# LEF file generated by Abstract Generator version 6.1.5
#
# Contains LEF for all bins.
# Options:   [ ] Antenna
#            [ ] Geometry
#            [x] Technology
# Design rule Document No.TD-LO40-DR-2001  Rev: 3R
# Antenna rule Document No.TD-LO40-DR-2004 Rev: 0T


VERSION 5.7 ;
NAMESCASESENSITIVE ON ;
BUSBITCHARS "[]" ;
DIVIDERCHAR "/" ;
UNITS
  DATABASE MICRONS 1000 ;
END UNITS

MANUFACTURINGGRID 0.001 ;
USEMINSPACING OBS OFF ;

PROPERTYDEFINITIONS
  LAYER LEF58_ENCLOSURE STRING ;
  LAYER LEF58_ENCLOSUREEDGE STRING ;
  LAYER LEF57_ANTENNAGATEPLUSDIFF STRING ;
  LAYER LEF58_ARRAYSPACING STRING ;
  LAYER LEF58_SPACING STRING ;
END PROPERTYDEFINITIONS

LAYER GT
  TYPE	MASTERSLICE ;
END GT

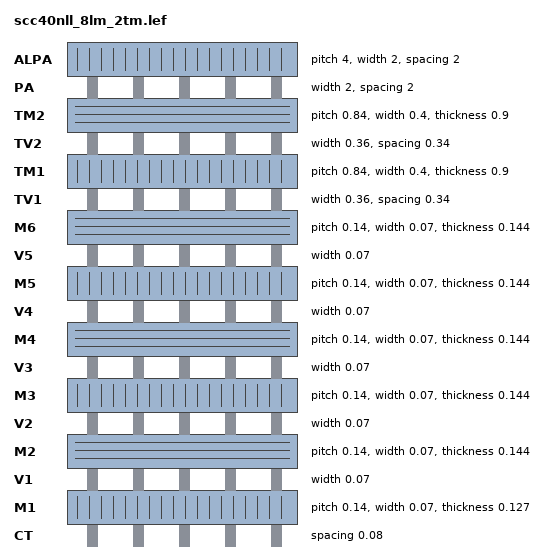
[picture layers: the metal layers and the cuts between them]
LAYER CT
  TYPE CUT ;
  SPACING 0.08 ;
  PROPERTY LEF58_ENCLOSUREEDGE "ENCLOSUREEDGE ABOVE 0.015 WIDTH 0.11 PARALLEL 0.265 WITHIN 0.085 ;"  ;
END CT

LAYER M1
  TYPE		ROUTING ;
  DIRECTION	VERTICAL ;
  PITCH		0.14 ;
  OFFSET	0.07 ;
  WIDTH		0.07 ;
  MINWIDTH 0.07 ;
  MAXWIDTH 4.5 ;
  MINSTEP 0.07 MAXEDGES 1 ;
  SPACINGTABLE TWOWIDTHS
    WIDTH     0.00                   0.070   0.080   0.120   0.30 
    WIDTH     0.215    PRL 0.2950    0.080   0.080   0.140   0.30 
    WIDTH     0.695    PRL 0.5950    0.120   0.140   0.120   0.30
    WIDTH     1.495    PRL 1.4950    0.300   0.300   0.300   0.30 ;
  MINIMUMCUT 2 WIDTH 0.24 WITHIN 0.16 FROMABOVE ;
  MINIMUMCUT 2 WIDTH 0.24 WITHIN 0.16 FROMABOVE LENGTH 0.24 WITHIN 1.105 ;
  MINIMUMCUT 2 WIDTH 0.26 FROMABOVE ;
  MINIMUMCUT 3 WIDTH 0.52 FROMABOVE ;
  MINIMUMCUT 4 WIDTH 0.645 FROMABOVE ;
  PROPERTY LEF58_SPACING "SPACING 0.08 ENDOFLINE 0.09 WITHIN 0.02 MINLENGTH 0.07 TWOSIDES
  PARALLELEDGE 0.08 WITHIN 0.065 ;" ;
  RESISTANCE	RPERSQ 0.308 ;
  CAPACITANCE	CPERSQDIST 3.92e-07 ;
  EDGECAPACITANCE 6.6700e-05 ;
  THICKNESS 0.127 ;
  ANTENNAMODEL OXIDE1 ;
  ANTENNACUMAREARATIO 5000.0 ;
  ANTENNACUMDIFFAREARATIO 44000.0 ;
  PROPERTY LEF57_ANTENNAGATEPLUSDIFF "ANTENNAGATEPLUSDIFF 500.0 ;" ;
  MINIMUMDENSITY 10 ;
  MAXIMUMDENSITY 85 ;
  DENSITYCHECKWINDOW 110 110 ;
  DENSITYCHECKSTEP 55 ;
  AREA	0.0196 ;
  MINENCLOSEDAREA  0.200 ;
END M1

LAYER V1
  TYPE	CUT ;
  WIDTH 0.07 ;
  PROPERTY LEF58_SPACING
  "SPACING 0.07 SAMENET ;" ;
   PROPERTY LEF58_SPACING "SPACING 0.09 ;" ;
   PROPERTY LEF58_SPACING "SPACING 0.10 PARALLELOVERLAP EXCEPTSAMENET ;" ;
  ARRAYSPACING CUTSPACING 0.09 ARRAYCUTS 3 SPACING 0.100 ;
  ENCLOSURE  0.015 0.015 ;
  ENCLOSURE  0.02 0.01 ;
  ENCLOSURE  0.0 0.03 ;
  ANTENNAMODEL OXIDE1 ;
  ANTENNAAREARATIO 20.0 ;
  ANTENNACUMDIFFAREARATIO 1000.0 ;
  PROPERTY LEF57_ANTENNAGATEPLUSDIFF "ANTENNAGATEPLUSDIFF 200.0 ;" ;
END V1

LAYER M2
  TYPE		ROUTING ;
  DIRECTION	HORIZONTAL ;
  PITCH		0.14 ;
  OFFSET        0.07 ;
  WIDTH		0.07 ;
  MINWIDTH 0.07 ;
  MAXWIDTH 4.5 ;
  MINSTEP 0.07 MAXEDGES 1 ;
  SPACINGTABLE    TWOWIDTHS
    WIDTH     0.00                 0.070   0.100   0.120   0.30 
    WIDTH     0.215    PRL 0.295   0.100   0.100   0.140   0.30 
    WIDTH     0.695    PRL 0.595   0.120   0.140   0.120   0.30
    WIDTH     1.495    PRL 1.495   0.300   0.300   0.300   0.30 ;
  MINIMUMCUT 2 WIDTH 0.24 WITHIN 0.16 ;
  MINIMUMCUT 2 WIDTH 0.24 WITHIN 0.16 LENGTH 0.24 WITHIN 1.105 ;
  MINIMUMCUT 2 WIDTH 0.26 ;
  MINIMUMCUT 3 WIDTH 0.52 ;
  MINIMUMCUT 4 WIDTH 0.645 ;
  PROPERTY LEF58_SPACING "SPACING 0.12 ENDOFLINE 0.1 WITHIN 0.031 PARALLELEDGE 0.08 WITHIN 0.095
  ENCLOSECUT 0.05 CUTSPACING 0.12 ;" ;
  PROPERTY LEF58_SPACING "SPACING 0.1 ENDOFLINE 0.1 WITHIN 0.031 MINLENGTH 0.07 TWOSIDES
  PARALLELEDGE 0.1 WITHIN 0.095 ;" ;
  RESISTANCE	RPERSQ 0.278 ;
  CAPACITANCE	CPERSQDIST 3.88e-07 ;
  EDGECAPACITANCE 5.8000e-05 ;
  THICKNESS 0.144 ;
  ANTENNAMODEL OXIDE1 ;
  ANTENNACUMAREARATIO 5000.0 ;
  ANTENNACUMDIFFAREARATIO 44000.0 ;
  PROPERTY LEF57_ANTENNAGATEPLUSDIFF "ANTENNAGATEPLUSDIFF 500.0 ;" ;
  MINIMUMDENSITY 10 ;
  MAXIMUMDENSITY 85 ;
  DENSITYCHECKWINDOW 110 110 ;
  DENSITYCHECKSTEP 55 ;
  AREA	0.0196 ;
  MINENCLOSEDAREA  0.200 ;
END M2

LAYER V2
  TYPE	CUT ;
  WIDTH 0.07 ;
  PROPERTY LEF58_SPACING
  "SPACING 0.07 SAMENET ;" ;
   PROPERTY LEF58_SPACING "SPACING 0.09 ;" ;
   PROPERTY LEF58_SPACING "SPACING 0.10 PARALLELOVERLAP EXCEPTSAMENET ;" ;
  ARRAYSPACING CUTSPACING 0.09 ARRAYCUTS 3 SPACING 0.100 ;
  ENCLOSURE  0.015 0.015 ;
  ENCLOSURE  0.02 0.01 ;
  ENCLOSURE  0.0 0.03 ;
  ANTENNAMODEL OXIDE1 ;
  ANTENNAAREARATIO 20.0 ;
  ANTENNACUMDIFFAREARATIO 1000.0 ;
  PROPERTY LEF57_ANTENNAGATEPLUSDIFF "ANTENNAGATEPLUSDIFF 200.0 ;" ;
END V2

LAYER M3
  TYPE		ROUTING ;
  DIRECTION	VERTICAL ;
  PITCH		0.14 ;
  OFFSET	0.07 ;
  WIDTH		0.07 ;
  MINWIDTH 0.07 ;
  MAXWIDTH 4.5 ;
  MINSTEP 0.07 MAXEDGES 1 ;
  SPACINGTABLE    TWOWIDTHS
    WIDTH     0.00                 0.070   0.100   0.120   0.30 
    WIDTH     0.215    PRL 0.295   0.100   0.100   0.140   0.30 
    WIDTH     0.695    PRL 0.595   0.120   0.140   0.120   0.30
    WIDTH     1.495    PRL 1.495   0.300   0.300   0.300   0.30 ;
  MINIMUMCUT 2 WIDTH 0.24 WITHIN 0.16 ;
  MINIMUMCUT 2 WIDTH 0.24 WITHIN 0.16 LENGTH 0.24 WITHIN 1.105 ;
  MINIMUMCUT 2 WIDTH 0.26 ;
  MINIMUMCUT 3 WIDTH 0.52 ;
  MINIMUMCUT 4 WIDTH 0.645 ;
  PROPERTY LEF58_SPACING "SPACING 0.12 ENDOFLINE 0.1 WITHIN 0.031 PARALLELEDGE 0.08 WITHIN 0.095
  ENCLOSECUT 0.05 CUTSPACING 0.12 ;" ;
  PROPERTY LEF58_SPACING "SPACING 0.1 ENDOFLINE 0.1 WITHIN 0.031 MINLENGTH 0.07 TWOSIDES
  PARALLELEDGE 0.1 WITHIN 0.095 ;" ;
  RESISTANCE	RPERSQ 0.278 ;
  CAPACITANCE	CPERSQDIST 3.88e-07 ;
  EDGECAPACITANCE 5.8000e-05 ;
  THICKNESS 0.144 ;
  ANTENNAMODEL OXIDE1 ;
  ANTENNACUMAREARATIO 5000.0 ;
  ANTENNACUMDIFFAREARATIO 44000.0 ;
  PROPERTY LEF57_ANTENNAGATEPLUSDIFF "ANTENNAGATEPLUSDIFF 500.0 ;" ;
  MINIMUMDENSITY 10 ;
  MAXIMUMDENSITY 85 ;
  DENSITYCHECKWINDOW 110 110 ;
  DENSITYCHECKSTEP 55 ;
  AREA	0.0196 ;
  MINENCLOSEDAREA  0.200 ;
END M3

LAYER V3
  TYPE	CUT ;
  WIDTH 0.07 ;
  PROPERTY LEF58_SPACING
  "SPACING 0.07 SAMENET ;" ;
   PROPERTY LEF58_SPACING "SPACING 0.09 ;" ;
   PROPERTY LEF58_SPACING "SPACING 0.10 PARALLELOVERLAP EXCEPTSAMENET ;" ;
  ARRAYSPACING CUTSPACING 0.09 ARRAYCUTS 3 SPACING 0.100 ;
  ENCLOSURE  0.015 0.015 ;
  ENCLOSURE  0.02 0.01 ;
  ENCLOSURE  0.0 0.03 ;
  ANTENNAMODEL OXIDE1 ;
  ANTENNAAREARATIO 20.0 ;
  ANTENNACUMDIFFAREARATIO 1000.0 ;
  PROPERTY LEF57_ANTENNAGATEPLUSDIFF "ANTENNAGATEPLUSDIFF 200.0 ;" ;
END V3

LAYER M4
  TYPE		ROUTING ;
  DIRECTION	HORIZONTAL ;
  PITCH		0.14 ;
  OFFSET        0.07 ;
  WIDTH		0.07 ;
  MINWIDTH 0.07 ;
  MAXWIDTH 4.5 ;
  MINSTEP 0.07 MAXEDGES 1 ;
  SPACINGTABLE    TWOWIDTHS
    WIDTH     0.00                 0.070   0.100   0.120   0.30 
    WIDTH     0.215    PRL 0.295   0.100   0.100   0.140   0.30 
    WIDTH     0.695    PRL 0.595   0.120   0.140   0.120   0.30
    WIDTH     1.495    PRL 1.495   0.300   0.300   0.300   0.30 ;
  MINIMUMCUT 2 WIDTH 0.24 WITHIN 0.16 ;
  MINIMUMCUT 2 WIDTH 0.24 WITHIN 0.16 LENGTH 0.24 WITHIN 1.105 ;
  MINIMUMCUT 2 WIDTH 0.26 ;
  MINIMUMCUT 3 WIDTH 0.52 ;
  MINIMUMCUT 4 WIDTH 0.645 ;
  PROPERTY LEF58_SPACING "SPACING 0.12 ENDOFLINE 0.1 WITHIN 0.031 PARALLELEDGE 0.08 WITHIN 0.095
  ENCLOSECUT 0.05 CUTSPACING 0.12 ;" ;
  PROPERTY LEF58_SPACING "SPACING 0.1 ENDOFLINE 0.1 WITHIN 0.031 MINLENGTH 0.07 TWOSIDES
  PARALLELEDGE 0.1 WITHIN 0.095 ;" ;
  RESISTANCE	RPERSQ 0.278 ;
  CAPACITANCE	CPERSQDIST 3.88e-07 ;
  EDGECAPACITANCE 5.8000e-05 ;
  THICKNESS 0.144 ;
  ANTENNAMODEL OXIDE1 ;
  ANTENNACUMAREARATIO 5000.0 ;
  ANTENNACUMDIFFAREARATIO 44000.0 ;
  PROPERTY LEF57_ANTENNAGATEPLUSDIFF "ANTENNAGATEPLUSDIFF 500.0 ;" ;
  MINIMUMDENSITY 10 ;
  MAXIMUMDENSITY 85 ;
  DENSITYCHECKWINDOW 110 110 ;
  DENSITYCHECKSTEP 55 ;
  AREA	0.0196 ;
  MINENCLOSEDAREA  0.200 ;
END M4

LAYER V4
  TYPE	CUT ;
  WIDTH 0.07 ;
  PROPERTY LEF58_SPACING
  "SPACING 0.07 SAMENET ;" ;
   PROPERTY LEF58_SPACING "SPACING 0.09 ;" ;
   PROPERTY LEF58_SPACING "SPACING 0.10 PARALLELOVERLAP EXCEPTSAMENET ;" ;
  ARRAYSPACING CUTSPACING 0.09 ARRAYCUTS 3 SPACING 0.100 ;
  ENCLOSURE  0.015 0.015 ;
  ENCLOSURE  0.02 0.01 ;
  ENCLOSURE  0.0 0.03 ;
  ANTENNAMODEL OXIDE1 ;
  ANTENNAAREARATIO 20.0 ;
  ANTENNACUMDIFFAREARATIO 1000.0 ;
  PROPERTY LEF57_ANTENNAGATEPLUSDIFF "ANTENNAGATEPLUSDIFF 200.0 ;" ;
END V4

LAYER M5
  TYPE          ROUTING ;
  DIRECTION     VERTICAL ;
  PITCH         0.14 ;
  OFFSET        0.07 ;
  WIDTH         0.07 ;
  MINWIDTH 0.07 ;
  MAXWIDTH 4.5 ;
  MINSTEP 0.07 MAXEDGES 1 ;
  SPACINGTABLE    TWOWIDTHS
    WIDTH     0.00                 0.070   0.100   0.120   0.30 
    WIDTH     0.215    PRL 0.295   0.100   0.100   0.140   0.30 
    WIDTH     0.695    PRL 0.595   0.120   0.140   0.120   0.30
    WIDTH     1.495    PRL 1.495   0.300   0.300   0.300   0.30 ;
  MINIMUMCUT 2 WIDTH 0.24 WITHIN 0.16 ;
  MINIMUMCUT 2 WIDTH 0.24 WITHIN 0.16 LENGTH 0.24 WITHIN 1.105 ;
  MINIMUMCUT 2 WIDTH 0.26 ;
  MINIMUMCUT 3 WIDTH 0.52 ;
  MINIMUMCUT 4 WIDTH 0.645 ;
  PROPERTY LEF58_SPACING "SPACING 0.12 ENDOFLINE 0.1 WITHIN 0.031 PARALLELEDGE 0.08 WITHIN 0.095
  ENCLOSECUT 0.05 CUTSPACING 0.12 ;" ;
  PROPERTY LEF58_SPACING "SPACING 0.1 ENDOFLINE 0.1 WITHIN 0.031 MINLENGTH 0.07 TWOSIDES
  PARALLELEDGE 0.1 WITHIN 0.095 ;" ;
  RESISTANCE    RPERSQ 0.278 ;
  CAPACITANCE	CPERSQDIST 3.88e-07 ;
  EDGECAPACITANCE 5.8000e-05 ;
  THICKNESS 0.144 ;
  ANTENNAMODEL OXIDE1 ;
  ANTENNACUMAREARATIO 5000.0 ;
  ANTENNACUMDIFFAREARATIO 44000.0 ;
  PROPERTY LEF57_ANTENNAGATEPLUSDIFF "ANTENNAGATEPLUSDIFF 500.0 ;" ;
  MINIMUMDENSITY 10 ;
  MAXIMUMDENSITY 85 ;
  DENSITYCHECKWINDOW 110 110 ;
  DENSITYCHECKSTEP 55 ;
  AREA  0.0196 ;
  MINENCLOSEDAREA  0.200 ;
END M5

LAYER V5
  TYPE  CUT ;
  WIDTH 0.07 ;
  PROPERTY LEF58_SPACING
  "SPACING 0.07 SAMENET ;" ;
   PROPERTY LEF58_SPACING "SPACING 0.09 ;" ;
   PROPERTY LEF58_SPACING "SPACING 0.10 PARALLELOVERLAP EXCEPTSAMENET ;" ;
  ARRAYSPACING CUTSPACING 0.09 ARRAYCUTS 3 SPACING 0.100 ;
  ENCLOSURE  0.015 0.015 ;
  ENCLOSURE  0.02 0.01 ;
  ENCLOSURE  0.0 0.03 ;
  ANTENNAMODEL OXIDE1 ;
  ANTENNAAREARATIO 20.0 ;
  ANTENNACUMDIFFAREARATIO 1000.0 ;
  PROPERTY LEF57_ANTENNAGATEPLUSDIFF "ANTENNAGATEPLUSDIFF 200.0 ;" ;
END V5

LAYER M6
  TYPE		ROUTING ;
  DIRECTION	HORIZONTAL ;
  PITCH		0.14 ;
  OFFSET        0.07 ;
  WIDTH		0.07 ;
  MINWIDTH 0.07 ;
  MAXWIDTH 4.5 ;
  MINSTEP 0.07 MAXEDGES 1 ;
  SPACINGTABLE    TWOWIDTHS
    WIDTH     0.00                 0.070   0.100   0.120   0.30 
    WIDTH     0.215    PRL 0.295   0.100   0.100   0.140   0.30 
    WIDTH     0.695    PRL 0.595   0.120   0.140   0.120   0.30
    WIDTH     1.495    PRL 1.495   0.300   0.300   0.300   0.30 ;
  MINIMUMCUT 2 WIDTH 0.24 WITHIN 0.16 FROMBELOW ;
  MINIMUMCUT 2 WIDTH 0.24 WITHIN 0.16 FROMBELOW LENGTH 0.24 WITHIN 1.105 ;
  MINIMUMCUT 2 WIDTH 0.26 FROMBELOW ;
  MINIMUMCUT 3 WIDTH 0.52 FROMBELOW ;
  MINIMUMCUT 4 WIDTH 0.645 FROMBELOW ;
  PROPERTY LEF58_SPACING "SPACING 0.12 ENDOFLINE 0.1 WITHIN 0.031 PARALLELEDGE 0.08 WITHIN 0.095
  ENCLOSECUT 0.05 CUTSPACING 0.12 ;" ;
  PROPERTY LEF58_SPACING "SPACING 0.1 ENDOFLINE 0.1 WITHIN 0.031 MINLENGTH 0.07 TWOSIDES
  PARALLELEDGE 0.1 WITHIN 0.095 ;" ;
  RESISTANCE    RPERSQ 0.278 ;
  CAPACITANCE	CPERSQDIST 3.88e-07 ;
  EDGECAPACITANCE 5.8000e-05 ;
  THICKNESS 0.144 ;
  ANTENNAMODEL OXIDE1 ;
  ANTENNACUMAREARATIO 5000.0 ;
  ANTENNACUMDIFFAREARATIO 44000.0 ;
  PROPERTY LEF57_ANTENNAGATEPLUSDIFF "ANTENNAGATEPLUSDIFF 500.0 ;" ;
  MINIMUMDENSITY 10 ;
  MAXIMUMDENSITY 85 ;
  DENSITYCHECKWINDOW 110 110 ;
  DENSITYCHECKSTEP 55 ;
  AREA  0.0196 ;
  MINENCLOSEDAREA  0.200 ;
END M6

LAYER TV1
  TYPE	CUT ;
  WIDTH 0.36 ;
#  SPACING 0.5 ;
  SPACING 0.34 SAMENET ;
  ARRAYSPACING CUTSPACING 0.50 ARRAYCUTS 3 SPACING 0.56 ;
  ENCLOSURE ABOVE 0.03 0.02 ;
  ENCLOSURE BELOW 0.05 0.01 ;
  ANTENNAMODEL OXIDE1 ;
  ANTENNAAREARATIO 20.0 ;
  ANTENNACUMDIFFAREARATIO 1000.0 ;
  PROPERTY LEF57_ANTENNAGATEPLUSDIFF "ANTENNAGATEPLUSDIFF 200.0 ;" ;
END TV1

LAYER TM1
  TYPE		ROUTING ;
  DIRECTION	VERTICAL ;
  PITCH		0.84 ;
  OFFSET	0.42 ;
  WIDTH		0.40 ;
  MINWIDTH 0.40 ;
  MAXWIDTH 12 ;
  MINSTEP 0.40 MAXEDGES 1 ;
  SPACINGTABLE    TWOWIDTHS
    WIDTH     0.00                0.40   0.50   1.20 
    WIDTH     2.00    PRL 1.50    0.50   0.50   1.20
    WIDTH     4.50    PRL 1.50    1.20   1.20   1.20 ;
  MINIMUMCUT 2 WIDTH 1.8 FROMABOVE ;
  RESISTANCE	RPERSQ 0.022 ;
  CAPACITANCE	CPERSQDIST 3.45e-07 ;
  EDGECAPACITANCE 6.99000e-05 ;
  THICKNESS 0.9 ;
  ANTENNAMODEL OXIDE1 ;
  ANTENNACUMAREARATIO 5000.0 ;
  ANTENNACUMDIFFAREARATIO 55000.0 ;
  PROPERTY LEF57_ANTENNAGATEPLUSDIFF "ANTENNAGATEPLUSDIFF 9984.0 ;" ;
  MINIMUMDENSITY 20 ;
  MAXIMUMDENSITY 85 ;
  DENSITYCHECKWINDOW 200 200 ;
  DENSITYCHECKSTEP 100 ;
  AREA  0.560 ;
  MINENCLOSEDAREA  0.80 ;
END TM1

LAYER TV2
  TYPE	CUT ;
  WIDTH 0.36 ;
#  SPACING 0.5 ;
  SPACING 0.34 SAMENET ;
  ARRAYSPACING CUTSPACING 0.50 ARRAYCUTS 3 SPACING 0.56 ;
  ENCLOSURE ABOVE 0.03 0.02 ;
  ENCLOSURE BELOW 0.05 0.01 ;
  ANTENNAMODEL OXIDE1 ;
  ANTENNAAREARATIO 20.0 ;
  ANTENNACUMDIFFAREARATIO 1000.0 ;
  PROPERTY LEF57_ANTENNAGATEPLUSDIFF "ANTENNAGATEPLUSDIFF 200.0 ;" ;
END TV2

LAYER TM2
  TYPE		ROUTING ;
  DIRECTION	HORIZONTAL ;
  PITCH		0.84 ;
  OFFSET	0.42 ;
  WIDTH		0.4 ;
  MINWIDTH 0.40 ;
  MAXWIDTH 12 ;
  MINSTEP 0.40 MAXEDGES 1 ;
  SPACINGTABLE    TWOWIDTHS
    WIDTH     0.00                0.40   0.50   1.20 
    WIDTH     2.00    PRL 1.50    0.50   0.50   1.20
    WIDTH     4.50    PRL 1.50    1.20   1.20   1.20 ;
  MINIMUMCUT 2 WIDTH 1.8 FROMBELOW ;
  RESISTANCE	RPERSQ 0.022 ;
  CAPACITANCE	CPERSQDIST 3.45e-07 ;
  EDGECAPACITANCE 6.99000e-05 ;
  THICKNESS 0.9 ;
  ANTENNAMODEL OXIDE1 ;
  ANTENNACUMAREARATIO 5000.0 ;
  ANTENNACUMDIFFAREARATIO 55000.0 ;
  PROPERTY LEF57_ANTENNAGATEPLUSDIFF "ANTENNAGATEPLUSDIFF 9984.0 ;" ;
  MINIMUMDENSITY 20 ;
  MAXIMUMDENSITY 85 ;
  DENSITYCHECKWINDOW 200 200 ;
  DENSITYCHECKSTEP 100 ;
  AREA  0.560 ;
  MINENCLOSEDAREA  0.80 ;
END TM2

LAYER PA
  TYPE CUT ;
  SPACING 2.0 ;
  WIDTH 2.00 ;
  ENCLOSURE ABOVE 0.5 0.5 ;
  ENCLOSURE BELOW 0.5 0.5 ;
  ANTENNAAREARATIO 200.0 ;
  ANTENNACUMDIFFAREARATIO 400.0 ;
  PROPERTY LEF57_ANTENNAGATEPLUSDIFF "ANTENNAGATEPLUSDIFF 100.0 ;" ;
END PA

LAYER ALPA
  TYPE ROUTING ;
  DIRECTION	VERTICAL ;
  PITCH 4.0 ;
  OFFSET 2.0 ;
  WIDTH 2.0 ;
  MINWIDTH 2.0 ;
  SPACING 2.0 ;
  ANTENNACUMAREARATIO 2000.0 ;
  ANTENNACUMDIFFAREARATIO 30000.0 ;
  PROPERTY LEF57_ANTENNAGATEPLUSDIFF "ANTENNAGATEPLUSDIFF 8500.0 ;" ;
END ALPA

LAYER OVERLAP
  TYPE OVERLAP ;
END OVERLAP

VIA V1_0_VV DEFAULT
    LAYER M1 ;
      RECT -0.035 -0.065 0.035 0.065 ;
    LAYER V1 ;
      RECT -0.035 -0.035 0.035 0.035 ;
    LAYER M2 ;
      RECT -0.035 -0.065 0.035 0.065 ;
END V1_0_VV

VIA V1_0_VH DEFAULT
    LAYER M1 ;
      RECT -0.035 -0.065 0.035 0.065 ;
    LAYER V1 ;
      RECT -0.035 -0.035 0.035 0.035 ;
    LAYER M2 ;
      RECT -0.065 -0.035 0.065 0.035 ;
END V1_0_VH

VIA V1_0_HV DEFAULT
    LAYER M1 ;
      RECT -0.065 -0.035 0.065 0.035 ;
    LAYER V1 ;
      RECT -0.035 -0.035 0.035 0.035 ;
    LAYER M2 ;
      RECT -0.035 -0.065 0.035 0.065 ;
END V1_0_HV

VIA V1_0_HH DEFAULT
    LAYER M1 ;
      RECT -0.065 -0.035 0.065 0.035 ;
    LAYER V1 ;
      RECT -0.035 -0.035 0.035 0.035 ;
    LAYER M2 ;
      RECT -0.065 -0.035 0.065 0.035 ;
END V1_0_HH

VIA V1_0_S2H_VH DEFAULT
    LAYER M1 ;
      RECT -0.105 -0.065 0.105 0.065 ;
    LAYER V1 ;
      RECT -0.105 -0.035 -0.035 0.035 ;
      RECT 0.035 -0.035 0.105 0.035 ;
    LAYER M2 ;
      RECT -0.135 -0.035 0.135 0.035 ;
END V1_0_S2H_VH

VIA V1_0_S2E_VH DEFAULT
    LAYER M1 ;
      RECT -0.035 -0.065 0.175 0.065 ;
    LAYER V1 ;
      RECT -0.035 -0.035 0.035 0.035 ;
      RECT 0.105 -0.035 0.175 0.035 ;
    LAYER M2 ;
      RECT -0.065 -0.035 0.205 0.035 ;
END V1_0_S2E_VH

VIA V1_0_S2N_VH DEFAULT
    LAYER M1 ;
      RECT -0.035 -0.065 0.035 0.205 ;
    LAYER V1 ;
      RECT -0.035 -0.035 0.035 0.035 ;
      RECT -0.035 0.105 0.035 0.175 ;
    LAYER M2 ;
      RECT -0.065 -0.035 0.065 0.175 ;
END V1_0_S2N_VH

VIA V1_0_S2W_VH DEFAULT
    LAYER M1 ;
      RECT -0.175 -0.065 0.035 0.065 ;
    LAYER V1 ;
      RECT -0.175 -0.035 -0.105 0.035 ;
      RECT -0.035 -0.035 0.035 0.035 ;
    LAYER M2 ;
      RECT -0.205 -0.035 0.065 0.035 ;
END V1_0_S2W_VH

VIA V1_0_S2S_VH DEFAULT
    LAYER M1 ;
      RECT -0.035 -0.205 0.035 0.065 ;
    LAYER V1 ;
      RECT -0.035 -0.035 0.035 0.035 ;
      RECT -0.035 -0.175 0.035 -0.105 ;
    LAYER M2 ;
      RECT -0.065 -0.175 0.065 0.035 ;
END V1_0_S2S_VH

VIA V1_0_S2V_VH DEFAULT
    LAYER M1 ;
      RECT -0.035 -0.135 0.035 0.135 ;
    LAYER V1 ;
      RECT -0.035 -0.105 0.035 -0.035 ;
      RECT -0.035 0.035 0.035 0.105 ;
    LAYER M2 ;
      RECT -0.065 -0.105 0.065 0.105 ;
END V1_0_S2V_VH

VIA V1_1_VV DEFAULT
    LAYER M1 ;
      RECT -0.035 -0.065 0.035 0.065 ;
    LAYER V1 ;
      RECT -0.035 -0.035 0.035 0.035 ;
    LAYER M2 ;
      RECT -0.045 -0.055 0.045 0.055 ;
END V1_1_VV

VIA V1_1_VH DEFAULT
    LAYER M1 ;
      RECT -0.035 -0.065 0.035 0.065 ;
    LAYER V1 ;
      RECT -0.035 -0.035 0.035 0.035 ;
    LAYER M2 ;
      RECT -0.055 -0.045 0.055 0.045 ;
END V1_1_VH

VIA V1_1_HV DEFAULT
    LAYER M1 ;
      RECT -0.065 -0.035 0.065 0.035 ;
    LAYER V1 ;
      RECT -0.035 -0.035 0.035 0.035 ;
    LAYER M2 ;
      RECT -0.045 -0.055 0.045 0.055 ;
END V1_1_HV

VIA V1_1_HH DEFAULT
    LAYER M1 ;
      RECT -0.065 -0.035 0.065 0.035 ;
    LAYER V1 ;
      RECT -0.035 -0.035 0.035 0.035 ;
    LAYER M2 ;
      RECT -0.055 -0.045 0.055 0.045 ;
END V1_1_HH

VIA V1_1_S2H_VH DEFAULT
    LAYER M1 ;
      RECT -0.105 -0.065 0.105 0.065 ;
    LAYER V1 ;
      RECT -0.105 -0.035 -0.035 0.035 ;
      RECT 0.035 -0.035 0.105 0.035 ;
    LAYER M2 ;
      RECT -0.125 -0.045 0.125 0.045 ;
END V1_1_S2H_VH

VIA V1_1_S2E_VH DEFAULT
    LAYER M1 ;
      RECT -0.035 -0.065 0.175 0.065 ;
    LAYER V1 ;
      RECT -0.035 -0.035 0.035 0.035 ;
      RECT 0.105 -0.035 0.175 0.035 ;
    LAYER M2 ;
      RECT -0.055 -0.045 0.195 0.045 ;
END V1_1_S2E_VH

VIA V1_1_S2N_VH DEFAULT
    LAYER M1 ;
      RECT -0.035 -0.065 0.035 0.205 ;
    LAYER V1 ;
      RECT -0.035 -0.035 0.035 0.035 ;
      RECT -0.035 0.105 0.035 0.175 ;
    LAYER M2 ;
      RECT -0.055 -0.045 0.055 0.185 ;
END V1_1_S2N_VH

VIA V1_1_S2W_VH DEFAULT
    LAYER M1 ;
      RECT -0.175 -0.065 0.035 0.065 ;
    LAYER V1 ;
      RECT -0.175 -0.035 -0.105 0.035 ;
      RECT -0.035 -0.035 0.035 0.035 ;
    LAYER M2 ;
      RECT -0.195 -0.045 0.055 0.045 ;
END V1_1_S2W_VH

VIA V1_1_S2S_VH DEFAULT
    LAYER M1 ;
      RECT -0.035 -0.205 0.035 0.065 ;
    LAYER V1 ;
      RECT -0.035 -0.035 0.035 0.035 ;
      RECT -0.035 -0.175 0.035 -0.105 ;
    LAYER M2 ;
      RECT -0.055 -0.185 0.055 0.045 ;
END V1_1_S2S_VH

VIA V1_1_S2V_VH DEFAULT
    LAYER M1 ;
      RECT -0.035 -0.135 0.035 0.135 ;
    LAYER V1 ;
      RECT -0.035 -0.105 0.035 -0.035 ;
      RECT -0.035 0.035 0.035 0.105 ;
    LAYER M2 ;
      RECT -0.055 -0.115 0.055 0.115 ;
END V1_1_S2V_VH

VIA V1_2_VX DEFAULT
    LAYER M1 ;
      RECT -0.035 -0.065 0.035 0.065 ;
    LAYER V1 ;
      RECT -0.035 -0.035 0.035 0.035 ;
    LAYER M2 ;
      RECT -0.05 -0.05 0.05 0.05 ;
END V1_2_VX

VIA V1_2_HX DEFAULT
    LAYER M1 ;
      RECT -0.065 -0.035 0.065 0.035 ;
    LAYER V1 ;
      RECT -0.035 -0.035 0.035 0.035 ;
    LAYER M2 ;
      RECT -0.05 -0.05 0.05 0.05 ;
END V1_2_HX

VIA V1_2_S2H_VX DEFAULT
    LAYER M1 ;
      RECT -0.105 -0.065 0.105 0.065 ;
    LAYER V1 ;
      RECT -0.105 -0.035 -0.035 0.035 ;
      RECT 0.035 -0.035 0.105 0.035 ;
    LAYER M2 ;
      RECT -0.12 -0.05 0.12 0.05 ;
END V1_2_S2H_VX

VIA V1_2_S2E_VX DEFAULT
    LAYER M1 ;
      RECT -0.035 -0.065 0.175 0.065 ;
    LAYER V1 ;
      RECT -0.035 -0.035 0.035 0.035 ;
      RECT 0.105 -0.035 0.175 0.035 ;
    LAYER M2 ;
      RECT -0.05 -0.05 0.19 0.05 ;
END V1_2_S2E_VX

VIA V1_2_S2N_VX DEFAULT
    LAYER M1 ;
      RECT -0.035 -0.065 0.035 0.205 ;
    LAYER V1 ;
      RECT -0.035 -0.035 0.035 0.035 ;
      RECT -0.035 0.105 0.035 0.175 ;
    LAYER M2 ;
      RECT -0.05 -0.05 0.05 0.19 ;
END V1_2_S2N_VX

VIA V1_2_S2W_VX DEFAULT
    LAYER M1 ;
      RECT -0.175 -0.065 0.035 0.065 ;
    LAYER V1 ;
      RECT -0.175 -0.035 -0.105 0.035 ;
      RECT -0.035 -0.035 0.035 0.035 ;
    LAYER M2 ;
      RECT -0.19 -0.05 0.05 0.05 ;
END V1_2_S2W_VX

VIA V1_2_S2S_VX DEFAULT
    LAYER M1 ;
      RECT -0.035 -0.205 0.035 0.065 ;
    LAYER V1 ;
      RECT -0.035 -0.035 0.035 0.035 ;
      RECT -0.035 -0.175 0.035 -0.105 ;
    LAYER M2 ;
      RECT -0.05 -0.19 0.05 0.05 ;
END V1_2_S2S_VX

VIA V1_2_S2V_VX DEFAULT
    LAYER M1 ;
      RECT -0.035 -0.135 0.035 0.135 ;
    LAYER V1 ;
      RECT -0.035 -0.105 0.035 -0.035 ;
      RECT -0.035 0.035 0.035 0.105 ;
    LAYER M2 ;
      RECT -0.05 -0.12 0.05 0.12 ;
END V1_2_S2V_VX

VIA V1_3_VV DEFAULT
    LAYER M1 ;
      RECT -0.045 -0.055 0.045 0.055 ;
    LAYER V1 ;
      RECT -0.035 -0.035 0.035 0.035 ;
    LAYER M2 ;
      RECT -0.035 -0.065 0.035 0.065 ;
END V1_3_VV

VIA V1_3_VH DEFAULT
    LAYER M1 ;
      RECT -0.045 -0.055 0.045 0.055 ;
    LAYER V1 ;
      RECT -0.035 -0.035 0.035 0.035 ;
    LAYER M2 ;
      RECT -0.065 -0.035 0.065 0.035 ;
END V1_3_VH

VIA V1_3_HV DEFAULT
    LAYER M1 ;
      RECT -0.055 -0.045 0.055 0.045 ;
    LAYER V1 ;
      RECT -0.035 -0.035 0.035 0.035 ;
    LAYER M2 ;
      RECT -0.035 -0.065 0.035 0.065 ;
END V1_3_HV

VIA V1_3_HH DEFAULT
    LAYER M1 ;
      RECT -0.055 -0.045 0.055 0.045 ;
    LAYER V1 ;
      RECT -0.035 -0.035 0.035 0.035 ;
    LAYER M2 ;
      RECT -0.065 -0.035 0.065 0.035 ;
END V1_3_HH

VIA V1_3_S2H_VH DEFAULT
    LAYER M1 ;
      RECT -0.115 -0.055 0.115 0.055 ;
    LAYER V1 ;
      RECT -0.105 -0.035 -0.035 0.035 ;
      RECT 0.035 -0.035 0.105 0.035 ;
    LAYER M2 ;
      RECT -0.135 -0.035 0.135 0.035 ;
END V1_3_S2H_VH

VIA V1_3_S2E_VH DEFAULT
    LAYER M1 ;
      RECT -0.045 -0.055 0.185 0.055 ;
    LAYER V1 ;
      RECT -0.035 -0.035 0.035 0.035 ;
      RECT 0.105 -0.035 0.175 0.035 ;
    LAYER M2 ;
      RECT -0.065 -0.035 0.205 0.035 ;
END V1_3_S2E_VH

VIA V1_3_S2N_VH DEFAULT
    LAYER M1 ;
      RECT -0.045 -0.055 0.045 0.195 ;
    LAYER V1 ;
      RECT -0.035 -0.035 0.035 0.035 ;
      RECT -0.035 0.105 0.035 0.175 ;
    LAYER M2 ;
      RECT -0.065 -0.035 0.065 0.175 ;
END V1_3_S2N_VH

VIA V1_3_S2W_VH DEFAULT
    LAYER M1 ;
      RECT -0.185 -0.055 0.045 0.055 ;
    LAYER V1 ;
      RECT -0.175 -0.035 -0.105 0.035 ;
      RECT -0.035 -0.035 0.035 0.035 ;
    LAYER M2 ;
      RECT -0.205 -0.035 0.065 0.035 ;
END V1_3_S2W_VH

VIA V1_3_S2S_VH DEFAULT
    LAYER M1 ;
      RECT -0.045 -0.195 0.045 0.055 ;
    LAYER V1 ;
      RECT -0.035 -0.035 0.035 0.035 ;
      RECT -0.035 -0.175 0.035 -0.105 ;
    LAYER M2 ;
      RECT -0.065 -0.175 0.065 0.035 ;
END V1_3_S2S_VH

VIA V1_3_S2V_VH DEFAULT
    LAYER M1 ;
      RECT -0.045 -0.125 0.045 0.125 ;
    LAYER V1 ;
      RECT -0.035 -0.105 0.035 -0.035 ;
      RECT -0.035 0.035 0.035 0.105 ;
    LAYER M2 ;
      RECT -0.065 -0.105 0.065 0.105 ;
END V1_3_S2V_VH

VIA V1_4_VV DEFAULT
    LAYER M1 ;
      RECT -0.045 -0.055 0.045 0.055 ;
    LAYER V1 ;
      RECT -0.035 -0.035 0.035 0.035 ;
    LAYER M2 ;
      RECT -0.045 -0.055 0.045 0.055 ;
END V1_4_VV

VIA V1_4_VH DEFAULT
    LAYER M1 ;
      RECT -0.045 -0.055 0.045 0.055 ;
    LAYER V1 ;
      RECT -0.035 -0.035 0.035 0.035 ;
    LAYER M2 ;
      RECT -0.055 -0.045 0.055 0.045 ;
END V1_4_VH

VIA V1_4_HV DEFAULT
    LAYER M1 ;
      RECT -0.055 -0.045 0.055 0.045 ;
    LAYER V1 ;
      RECT -0.035 -0.035 0.035 0.035 ;
    LAYER M2 ;
      RECT -0.045 -0.055 0.045 0.055 ;
END V1_4_HV

VIA V1_4_HH DEFAULT
    LAYER M1 ;
      RECT -0.055 -0.045 0.055 0.045 ;
    LAYER V1 ;
      RECT -0.035 -0.035 0.035 0.035 ;
    LAYER M2 ;
      RECT -0.055 -0.045 0.055 0.045 ;
END V1_4_HH

VIA V1_4_S2H_VH DEFAULT
    LAYER M1 ;
      RECT -0.115 -0.055 0.115 0.055 ;
    LAYER V1 ;
      RECT -0.105 -0.035 -0.035 0.035 ;
      RECT 0.035 -0.035 0.105 0.035 ;
    LAYER M2 ;
      RECT -0.125 -0.045 0.125 0.045 ;
END V1_4_S2H_VH

VIA V1_4_S2E_VH DEFAULT
    LAYER M1 ;
      RECT -0.045 -0.055 0.185 0.055 ;
    LAYER V1 ;
      RECT -0.035 -0.035 0.035 0.035 ;
      RECT 0.105 -0.035 0.175 0.035 ;
    LAYER M2 ;
      RECT -0.055 -0.045 0.195 0.045 ;
END V1_4_S2E_VH

VIA V1_4_S2N_VH DEFAULT
    LAYER M1 ;
      RECT -0.045 -0.055 0.045 0.195 ;
    LAYER V1 ;
      RECT -0.035 -0.035 0.035 0.035 ;
      RECT -0.035 0.105 0.035 0.175 ;
    LAYER M2 ;
      RECT -0.055 -0.045 0.055 0.185 ;
END V1_4_S2N_VH

VIA V1_4_S2W_VH DEFAULT
    LAYER M1 ;
      RECT -0.185 -0.055 0.045 0.055 ;
    LAYER V1 ;
      RECT -0.175 -0.035 -0.105 0.035 ;
      RECT -0.035 -0.035 0.035 0.035 ;
    LAYER M2 ;
      RECT -0.195 -0.045 0.055 0.045 ;
END V1_4_S2W_VH

VIA V1_4_S2S_VH DEFAULT
    LAYER M1 ;
      RECT -0.045 -0.195 0.045 0.055 ;
    LAYER V1 ;
      RECT -0.035 -0.035 0.035 0.035 ;
      RECT -0.035 -0.175 0.035 -0.105 ;
    LAYER M2 ;
      RECT -0.055 -0.185 0.055 0.045 ;
END V1_4_S2S_VH

VIA V1_4_S2V_VH DEFAULT
    LAYER M1 ;
      RECT -0.045 -0.125 0.045 0.125 ;
    LAYER V1 ;
      RECT -0.035 -0.105 0.035 -0.035 ;
      RECT -0.035 0.035 0.035 0.105 ;
    LAYER M2 ;
      RECT -0.055 -0.115 0.055 0.115 ;
END V1_4_S2V_VH

VIA V1_5_VX DEFAULT
    LAYER M1 ;
      RECT -0.045 -0.055 0.045 0.055 ;
    LAYER V1 ;
      RECT -0.035 -0.035 0.035 0.035 ;
    LAYER M2 ;
      RECT -0.05 -0.05 0.05 0.05 ;
END V1_5_VX

VIA V1_5_HX DEFAULT
    LAYER M1 ;
      RECT -0.055 -0.045 0.055 0.045 ;
    LAYER V1 ;
      RECT -0.035 -0.035 0.035 0.035 ;
    LAYER M2 ;
      RECT -0.05 -0.05 0.05 0.05 ;
END V1_5_HX

VIA V1_5_S2H_VX DEFAULT
    LAYER M1 ;
      RECT -0.115 -0.055 0.115 0.055 ;
    LAYER V1 ;
      RECT -0.105 -0.035 -0.035 0.035 ;
      RECT 0.035 -0.035 0.105 0.035 ;
    LAYER M2 ;
      RECT -0.12 -0.05 0.12 0.05 ;
END V1_5_S2H_VX

VIA V1_5_S2E_VX DEFAULT
    LAYER M1 ;
      RECT -0.045 -0.055 0.185 0.055 ;
    LAYER V1 ;
      RECT -0.035 -0.035 0.035 0.035 ;
      RECT 0.105 -0.035 0.175 0.035 ;
    LAYER M2 ;
      RECT -0.05 -0.05 0.19 0.05 ;
END V1_5_S2E_VX

VIA V1_5_S2N_VX DEFAULT
    LAYER M1 ;
      RECT -0.045 -0.055 0.045 0.195 ;
    LAYER V1 ;
      RECT -0.035 -0.035 0.035 0.035 ;
      RECT -0.035 0.105 0.035 0.175 ;
    LAYER M2 ;
      RECT -0.05 -0.05 0.05 0.19 ;
END V1_5_S2N_VX

VIA V1_5_S2W_VX DEFAULT
    LAYER M1 ;
      RECT -0.185 -0.055 0.045 0.055 ;
    LAYER V1 ;
      RECT -0.175 -0.035 -0.105 0.035 ;
      RECT -0.035 -0.035 0.035 0.035 ;
    LAYER M2 ;
      RECT -0.19 -0.05 0.05 0.05 ;
END V1_5_S2W_VX

VIA V1_5_S2S_VX DEFAULT
    LAYER M1 ;
      RECT -0.045 -0.195 0.045 0.055 ;
    LAYER V1 ;
      RECT -0.035 -0.035 0.035 0.035 ;
      RECT -0.035 -0.175 0.035 -0.105 ;
    LAYER M2 ;
      RECT -0.05 -0.19 0.05 0.05 ;
END V1_5_S2S_VX

VIA V1_5_S2V_VX DEFAULT
    LAYER M1 ;
      RECT -0.045 -0.125 0.045 0.125 ;
    LAYER V1 ;
      RECT -0.035 -0.105 0.035 -0.035 ;
      RECT -0.035 0.035 0.035 0.105 ;
    LAYER M2 ;
      RECT -0.05 -0.12 0.05 0.12 ;
END V1_5_S2V_VX

VIA V1_6_XV DEFAULT
    LAYER M1 ;
      RECT -0.05 -0.05 0.05 0.05 ;
    LAYER V1 ;
      RECT -0.035 -0.035 0.035 0.035 ;
    LAYER M2 ;
      RECT -0.035 -0.065 0.035 0.065 ;
END V1_6_XV

VIA V1_6_XH DEFAULT
    LAYER M1 ;
      RECT -0.05 -0.05 0.05 0.05 ;
    LAYER V1 ;
      RECT -0.035 -0.035 0.035 0.035 ;
    LAYER M2 ;
      RECT -0.065 -0.035 0.065 0.035 ;
END V1_6_XH

VIA V1_6_S2H_XH DEFAULT
    LAYER M1 ;
      RECT -0.12 -0.05 0.12 0.05 ;
    LAYER V1 ;
      RECT -0.105 -0.035 -0.035 0.035 ;
      RECT 0.035 -0.035 0.105 0.035 ;
    LAYER M2 ;
      RECT -0.135 -0.035 0.135 0.035 ;
END V1_6_S2H_XH

VIA V1_6_S2E_XH DEFAULT
    LAYER M1 ;
      RECT -0.05 -0.05 0.19 0.05 ;
    LAYER V1 ;
      RECT -0.035 -0.035 0.035 0.035 ;
      RECT 0.105 -0.035 0.175 0.035 ;
    LAYER M2 ;
      RECT -0.065 -0.035 0.205 0.035 ;
END V1_6_S2E_XH

VIA V1_6_S2N_XH DEFAULT
    LAYER M1 ;
      RECT -0.05 -0.05 0.05 0.19 ;
    LAYER V1 ;
      RECT -0.035 -0.035 0.035 0.035 ;
      RECT -0.035 0.105 0.035 0.175 ;
    LAYER M2 ;
      RECT -0.065 -0.035 0.065 0.175 ;
END V1_6_S2N_XH

VIA V1_6_S2W_XH DEFAULT
    LAYER M1 ;
      RECT -0.19 -0.05 0.05 0.05 ;
    LAYER V1 ;
      RECT -0.175 -0.035 -0.105 0.035 ;
      RECT -0.035 -0.035 0.035 0.035 ;
    LAYER M2 ;
      RECT -0.205 -0.035 0.065 0.035 ;
END V1_6_S2W_XH

VIA V1_6_S2S_XH DEFAULT
    LAYER M1 ;
      RECT -0.05 -0.19 0.05 0.05 ;
    LAYER V1 ;
      RECT -0.035 -0.035 0.035 0.035 ;
      RECT -0.035 -0.175 0.035 -0.105 ;
    LAYER M2 ;
      RECT -0.065 -0.175 0.065 0.035 ;
END V1_6_S2S_XH

VIA V1_6_S2V_XH DEFAULT
    LAYER M1 ;
      RECT -0.05 -0.12 0.05 0.12 ;
    LAYER V1 ;
      RECT -0.035 -0.105 0.035 -0.035 ;
      RECT -0.035 0.035 0.035 0.105 ;
    LAYER M2 ;
      RECT -0.065 -0.105 0.065 0.105 ;
END V1_6_S2V_XH

VIA V1_7_XV DEFAULT
    LAYER M1 ;
      RECT -0.05 -0.05 0.05 0.05 ;
    LAYER V1 ;
      RECT -0.035 -0.035 0.035 0.035 ;
    LAYER M2 ;
      RECT -0.045 -0.055 0.045 0.055 ;
END V1_7_XV

VIA V1_7_XH DEFAULT
    LAYER M1 ;
      RECT -0.05 -0.05 0.05 0.05 ;
    LAYER V1 ;
      RECT -0.035 -0.035 0.035 0.035 ;
    LAYER M2 ;
      RECT -0.055 -0.045 0.055 0.045 ;
END V1_7_XH

VIA V1_7_S2H_XH DEFAULT
    LAYER M1 ;
      RECT -0.12 -0.05 0.12 0.05 ;
    LAYER V1 ;
      RECT -0.105 -0.035 -0.035 0.035 ;
      RECT 0.035 -0.035 0.105 0.035 ;
    LAYER M2 ;
      RECT -0.125 -0.045 0.125 0.045 ;
END V1_7_S2H_XH

VIA V1_7_S2E_XH DEFAULT
    LAYER M1 ;
      RECT -0.05 -0.05 0.19 0.05 ;
    LAYER V1 ;
      RECT -0.035 -0.035 0.035 0.035 ;
      RECT 0.105 -0.035 0.175 0.035 ;
    LAYER M2 ;
      RECT -0.055 -0.045 0.195 0.045 ;
END V1_7_S2E_XH

VIA V1_7_S2N_XH DEFAULT
    LAYER M1 ;
      RECT -0.05 -0.05 0.05 0.19 ;
    LAYER V1 ;
      RECT -0.035 -0.035 0.035 0.035 ;
      RECT -0.035 0.105 0.035 0.175 ;
    LAYER M2 ;
      RECT -0.055 -0.045 0.055 0.185 ;
END V1_7_S2N_XH

VIA V1_7_S2W_XH DEFAULT
    LAYER M1 ;
      RECT -0.19 -0.05 0.05 0.05 ;
    LAYER V1 ;
      RECT -0.175 -0.035 -0.105 0.035 ;
      RECT -0.035 -0.035 0.035 0.035 ;
    LAYER M2 ;
      RECT -0.195 -0.045 0.055 0.045 ;
END V1_7_S2W_XH

VIA V1_7_S2S_XH DEFAULT
    LAYER M1 ;
      RECT -0.05 -0.19 0.05 0.05 ;
    LAYER V1 ;
      RECT -0.035 -0.035 0.035 0.035 ;
      RECT -0.035 -0.175 0.035 -0.105 ;
    LAYER M2 ;
      RECT -0.055 -0.185 0.055 0.045 ;
END V1_7_S2S_XH

VIA V1_7_S2V_XH DEFAULT
    LAYER M1 ;
      RECT -0.05 -0.12 0.05 0.12 ;
    LAYER V1 ;
      RECT -0.035 -0.105 0.035 -0.035 ;
      RECT -0.035 0.035 0.035 0.105 ;
    LAYER M2 ;
      RECT -0.055 -0.115 0.055 0.115 ;
END V1_7_S2V_XH

VIA V1_8_XX DEFAULT
    LAYER M1 ;
      RECT -0.05 -0.05 0.05 0.05 ;
    LAYER V1 ;
      RECT -0.035 -0.035 0.035 0.035 ;
    LAYER M2 ;
      RECT -0.05 -0.05 0.05 0.05 ;
END V1_8_XX

VIA V1_8_S2H_XX DEFAULT
    LAYER M1 ;
      RECT -0.12 -0.05 0.12 0.05 ;
    LAYER V1 ;
      RECT -0.105 -0.035 -0.035 0.035 ;
      RECT 0.035 -0.035 0.105 0.035 ;
    LAYER M2 ;
      RECT -0.12 -0.05 0.12 0.05 ;
END V1_8_S2H_XX

VIA V1_8_S2E_XX DEFAULT
    LAYER M1 ;
      RECT -0.05 -0.05 0.19 0.05 ;
    LAYER V1 ;
      RECT -0.035 -0.035 0.035 0.035 ;
      RECT 0.105 -0.035 0.175 0.035 ;
    LAYER M2 ;
      RECT -0.05 -0.05 0.19 0.05 ;
END V1_8_S2E_XX

VIA V1_8_S2N_XX DEFAULT
    LAYER M1 ;
      RECT -0.05 -0.05 0.05 0.19 ;
    LAYER V1 ;
      RECT -0.035 -0.035 0.035 0.035 ;
      RECT -0.035 0.105 0.035 0.175 ;
    LAYER M2 ;
      RECT -0.05 -0.05 0.05 0.19 ;
END V1_8_S2N_XX

VIA V1_8_S2W_XX DEFAULT
    LAYER M1 ;
      RECT -0.19 -0.05 0.05 0.05 ;
    LAYER V1 ;
      RECT -0.175 -0.035 -0.105 0.035 ;
      RECT -0.035 -0.035 0.035 0.035 ;
    LAYER M2 ;
      RECT -0.19 -0.05 0.05 0.05 ;
END V1_8_S2W_XX

VIA V1_8_S2S_XX DEFAULT
    LAYER M1 ;
      RECT -0.05 -0.19 0.05 0.05 ;
    LAYER V1 ;
      RECT -0.035 -0.035 0.035 0.035 ;
      RECT -0.035 -0.175 0.035 -0.105 ;
    LAYER M2 ;
      RECT -0.05 -0.19 0.05 0.05 ;
END V1_8_S2S_XX

VIA V1_8_S2V_XX DEFAULT
    LAYER M1 ;
      RECT -0.05 -0.12 0.05 0.12 ;
    LAYER V1 ;
      RECT -0.035 -0.105 0.035 -0.035 ;
      RECT -0.035 0.035 0.035 0.105 ;
    LAYER M2 ;
      RECT -0.05 -0.12 0.05 0.12 ;
END V1_8_S2V_XX

VIA V2_0_VV DEFAULT
    LAYER M2 ;
      RECT -0.035 -0.065 0.035 0.065 ;
    LAYER V2 ;
      RECT -0.035 -0.035 0.035 0.035 ;
    LAYER M3 ;
      RECT -0.035 -0.065 0.035 0.065 ;
END V2_0_VV

VIA V2_0_VH DEFAULT
    LAYER M2 ;
      RECT -0.035 -0.065 0.035 0.065 ;
    LAYER V2 ;
      RECT -0.035 -0.035 0.035 0.035 ;
    LAYER M3 ;
      RECT -0.065 -0.035 0.065 0.035 ;
END V2_0_VH

VIA V2_0_HV DEFAULT
    LAYER M2 ;
      RECT -0.065 -0.035 0.065 0.035 ;
    LAYER V2 ;
      RECT -0.035 -0.035 0.035 0.035 ;
    LAYER M3 ;
      RECT -0.035 -0.065 0.035 0.065 ;
END V2_0_HV

VIA V2_0_HH DEFAULT
    LAYER M2 ;
      RECT -0.065 -0.035 0.065 0.035 ;
    LAYER V2 ;
      RECT -0.035 -0.035 0.035 0.035 ;
    LAYER M3 ;
      RECT -0.065 -0.035 0.065 0.035 ;
END V2_0_HH

VIA V2_0_S2H_VH DEFAULT
    LAYER M2 ;
      RECT -0.105 -0.065 0.105 0.065 ;
    LAYER V2 ;
      RECT -0.105 -0.035 -0.035 0.035 ;
      RECT 0.035 -0.035 0.105 0.035 ;
    LAYER M3 ;
      RECT -0.135 -0.035 0.135 0.035 ;
END V2_0_S2H_VH

VIA V2_0_S2E_VH DEFAULT
    LAYER M2 ;
      RECT -0.035 -0.065 0.175 0.065 ;
    LAYER V2 ;
      RECT -0.035 -0.035 0.035 0.035 ;
      RECT 0.105 -0.035 0.175 0.035 ;
    LAYER M3 ;
      RECT -0.065 -0.035 0.205 0.035 ;
END V2_0_S2E_VH

VIA V2_0_S2N_VH DEFAULT
    LAYER M2 ;
      RECT -0.035 -0.065 0.035 0.205 ;
    LAYER V2 ;
      RECT -0.035 -0.035 0.035 0.035 ;
      RECT -0.035 0.105 0.035 0.175 ;
    LAYER M3 ;
      RECT -0.065 -0.035 0.065 0.175 ;
END V2_0_S2N_VH

VIA V2_0_S2W_VH DEFAULT
    LAYER M2 ;
      RECT -0.175 -0.065 0.035 0.065 ;
    LAYER V2 ;
      RECT -0.175 -0.035 -0.105 0.035 ;
      RECT -0.035 -0.035 0.035 0.035 ;
    LAYER M3 ;
      RECT -0.205 -0.035 0.065 0.035 ;
END V2_0_S2W_VH

VIA V2_0_S2S_VH DEFAULT
    LAYER M2 ;
      RECT -0.035 -0.205 0.035 0.065 ;
    LAYER V2 ;
      RECT -0.035 -0.035 0.035 0.035 ;
      RECT -0.035 -0.175 0.035 -0.105 ;
    LAYER M3 ;
      RECT -0.065 -0.175 0.065 0.035 ;
END V2_0_S2S_VH

VIA V2_0_S2V_VH DEFAULT
    LAYER M2 ;
      RECT -0.035 -0.135 0.035 0.135 ;
    LAYER V2 ;
      RECT -0.035 -0.105 0.035 -0.035 ;
      RECT -0.035 0.035 0.035 0.105 ;
    LAYER M3 ;
      RECT -0.065 -0.105 0.065 0.105 ;
END V2_0_S2V_VH

VIA V2_1_VV DEFAULT
    LAYER M2 ;
      RECT -0.035 -0.065 0.035 0.065 ;
    LAYER V2 ;
      RECT -0.035 -0.035 0.035 0.035 ;
    LAYER M3 ;
      RECT -0.045 -0.055 0.045 0.055 ;
END V2_1_VV

VIA V2_1_VH DEFAULT
    LAYER M2 ;
      RECT -0.035 -0.065 0.035 0.065 ;
    LAYER V2 ;
      RECT -0.035 -0.035 0.035 0.035 ;
    LAYER M3 ;
      RECT -0.055 -0.045 0.055 0.045 ;
END V2_1_VH

VIA V2_1_HV DEFAULT
    LAYER M2 ;
      RECT -0.065 -0.035 0.065 0.035 ;
    LAYER V2 ;
      RECT -0.035 -0.035 0.035 0.035 ;
    LAYER M3 ;
      RECT -0.045 -0.055 0.045 0.055 ;
END V2_1_HV

VIA V2_1_HH DEFAULT
    LAYER M2 ;
      RECT -0.065 -0.035 0.065 0.035 ;
    LAYER V2 ;
      RECT -0.035 -0.035 0.035 0.035 ;
    LAYER M3 ;
      RECT -0.055 -0.045 0.055 0.045 ;
END V2_1_HH

VIA V2_1_S2H_VH DEFAULT
    LAYER M2 ;
      RECT -0.105 -0.065 0.105 0.065 ;
    LAYER V2 ;
      RECT -0.105 -0.035 -0.035 0.035 ;
      RECT 0.035 -0.035 0.105 0.035 ;
    LAYER M3 ;
      RECT -0.125 -0.045 0.125 0.045 ;
END V2_1_S2H_VH

VIA V2_1_S2E_VH DEFAULT
    LAYER M2 ;
      RECT -0.035 -0.065 0.175 0.065 ;
    LAYER V2 ;
      RECT -0.035 -0.035 0.035 0.035 ;
      RECT 0.105 -0.035 0.175 0.035 ;
    LAYER M3 ;
      RECT -0.055 -0.045 0.195 0.045 ;
END V2_1_S2E_VH

VIA V2_1_S2N_VH DEFAULT
    LAYER M2 ;
      RECT -0.035 -0.065 0.035 0.205 ;
    LAYER V2 ;
      RECT -0.035 -0.035 0.035 0.035 ;
      RECT -0.035 0.105 0.035 0.175 ;
    LAYER M3 ;
      RECT -0.055 -0.045 0.055 0.185 ;
END V2_1_S2N_VH

VIA V2_1_S2W_VH DEFAULT
    LAYER M2 ;
      RECT -0.175 -0.065 0.035 0.065 ;
    LAYER V2 ;
      RECT -0.175 -0.035 -0.105 0.035 ;
      RECT -0.035 -0.035 0.035 0.035 ;
    LAYER M3 ;
      RECT -0.195 -0.045 0.055 0.045 ;
END V2_1_S2W_VH

VIA V2_1_S2S_VH DEFAULT
    LAYER M2 ;
      RECT -0.035 -0.205 0.035 0.065 ;
    LAYER V2 ;
      RECT -0.035 -0.035 0.035 0.035 ;
      RECT -0.035 -0.175 0.035 -0.105 ;
    LAYER M3 ;
      RECT -0.055 -0.185 0.055 0.045 ;
END V2_1_S2S_VH

VIA V2_1_S2V_VH DEFAULT
    LAYER M2 ;
      RECT -0.035 -0.135 0.035 0.135 ;
    LAYER V2 ;
      RECT -0.035 -0.105 0.035 -0.035 ;
      RECT -0.035 0.035 0.035 0.105 ;
    LAYER M3 ;
      RECT -0.055 -0.115 0.055 0.115 ;
END V2_1_S2V_VH

VIA V2_2_VX DEFAULT
    LAYER M2 ;
      RECT -0.035 -0.065 0.035 0.065 ;
    LAYER V2 ;
      RECT -0.035 -0.035 0.035 0.035 ;
    LAYER M3 ;
      RECT -0.05 -0.05 0.05 0.05 ;
END V2_2_VX

VIA V2_2_HX DEFAULT
    LAYER M2 ;
      RECT -0.065 -0.035 0.065 0.035 ;
    LAYER V2 ;
      RECT -0.035 -0.035 0.035 0.035 ;
    LAYER M3 ;
      RECT -0.05 -0.05 0.05 0.05 ;
END V2_2_HX

VIA V2_2_S2H_VX DEFAULT
    LAYER M2 ;
      RECT -0.105 -0.065 0.105 0.065 ;
    LAYER V2 ;
      RECT -0.105 -0.035 -0.035 0.035 ;
      RECT 0.035 -0.035 0.105 0.035 ;
    LAYER M3 ;
      RECT -0.12 -0.05 0.12 0.05 ;
END V2_2_S2H_VX

VIA V2_2_S2E_VX DEFAULT
    LAYER M2 ;
      RECT -0.035 -0.065 0.175 0.065 ;
    LAYER V2 ;
      RECT -0.035 -0.035 0.035 0.035 ;
      RECT 0.105 -0.035 0.175 0.035 ;
    LAYER M3 ;
      RECT -0.05 -0.05 0.19 0.05 ;
END V2_2_S2E_VX

VIA V2_2_S2N_VX DEFAULT
    LAYER M2 ;
      RECT -0.035 -0.065 0.035 0.205 ;
    LAYER V2 ;
      RECT -0.035 -0.035 0.035 0.035 ;
      RECT -0.035 0.105 0.035 0.175 ;
    LAYER M3 ;
      RECT -0.05 -0.05 0.05 0.19 ;
END V2_2_S2N_VX

VIA V2_2_S2W_VX DEFAULT
    LAYER M2 ;
      RECT -0.175 -0.065 0.035 0.065 ;
    LAYER V2 ;
      RECT -0.175 -0.035 -0.105 0.035 ;
      RECT -0.035 -0.035 0.035 0.035 ;
    LAYER M3 ;
      RECT -0.19 -0.05 0.05 0.05 ;
END V2_2_S2W_VX

VIA V2_2_S2S_VX DEFAULT
    LAYER M2 ;
      RECT -0.035 -0.205 0.035 0.065 ;
    LAYER V2 ;
      RECT -0.035 -0.035 0.035 0.035 ;
      RECT -0.035 -0.175 0.035 -0.105 ;
    LAYER M3 ;
      RECT -0.05 -0.19 0.05 0.05 ;
END V2_2_S2S_VX

VIA V2_2_S2V_VX DEFAULT
    LAYER M2 ;
      RECT -0.035 -0.135 0.035 0.135 ;
    LAYER V2 ;
      RECT -0.035 -0.105 0.035 -0.035 ;
      RECT -0.035 0.035 0.035 0.105 ;
    LAYER M3 ;
      RECT -0.05 -0.12 0.05 0.12 ;
END V2_2_S2V_VX

VIA V2_3_VV DEFAULT
    LAYER M2 ;
      RECT -0.045 -0.055 0.045 0.055 ;
    LAYER V2 ;
      RECT -0.035 -0.035 0.035 0.035 ;
    LAYER M3 ;
      RECT -0.035 -0.065 0.035 0.065 ;
END V2_3_VV

VIA V2_3_VH DEFAULT
    LAYER M2 ;
      RECT -0.045 -0.055 0.045 0.055 ;
    LAYER V2 ;
      RECT -0.035 -0.035 0.035 0.035 ;
    LAYER M3 ;
      RECT -0.065 -0.035 0.065 0.035 ;
END V2_3_VH

VIA V2_3_HV DEFAULT
    LAYER M2 ;
      RECT -0.055 -0.045 0.055 0.045 ;
    LAYER V2 ;
      RECT -0.035 -0.035 0.035 0.035 ;
    LAYER M3 ;
      RECT -0.035 -0.065 0.035 0.065 ;
END V2_3_HV

VIA V2_3_HH DEFAULT
    LAYER M2 ;
      RECT -0.055 -0.045 0.055 0.045 ;
    LAYER V2 ;
      RECT -0.035 -0.035 0.035 0.035 ;
    LAYER M3 ;
      RECT -0.065 -0.035 0.065 0.035 ;
END V2_3_HH

VIA V2_3_S2H_VH DEFAULT
    LAYER M2 ;
      RECT -0.115 -0.055 0.115 0.055 ;
    LAYER V2 ;
      RECT -0.105 -0.035 -0.035 0.035 ;
      RECT 0.035 -0.035 0.105 0.035 ;
    LAYER M3 ;
      RECT -0.135 -0.035 0.135 0.035 ;
END V2_3_S2H_VH

VIA V2_3_S2E_VH DEFAULT
    LAYER M2 ;
      RECT -0.045 -0.055 0.185 0.055 ;
    LAYER V2 ;
      RECT -0.035 -0.035 0.035 0.035 ;
      RECT 0.105 -0.035 0.175 0.035 ;
    LAYER M3 ;
      RECT -0.065 -0.035 0.205 0.035 ;
END V2_3_S2E_VH

VIA V2_3_S2N_VH DEFAULT
    LAYER M2 ;
      RECT -0.045 -0.055 0.045 0.195 ;
    LAYER V2 ;
      RECT -0.035 -0.035 0.035 0.035 ;
      RECT -0.035 0.105 0.035 0.175 ;
    LAYER M3 ;
      RECT -0.065 -0.035 0.065 0.175 ;
END V2_3_S2N_VH

VIA V2_3_S2W_VH DEFAULT
    LAYER M2 ;
      RECT -0.185 -0.055 0.045 0.055 ;
    LAYER V2 ;
      RECT -0.175 -0.035 -0.105 0.035 ;
      RECT -0.035 -0.035 0.035 0.035 ;
    LAYER M3 ;
      RECT -0.205 -0.035 0.065 0.035 ;
END V2_3_S2W_VH

VIA V2_3_S2S_VH DEFAULT
    LAYER M2 ;
      RECT -0.045 -0.195 0.045 0.055 ;
    LAYER V2 ;
      RECT -0.035 -0.035 0.035 0.035 ;
      RECT -0.035 -0.175 0.035 -0.105 ;
    LAYER M3 ;
      RECT -0.065 -0.175 0.065 0.035 ;
END V2_3_S2S_VH

VIA V2_3_S2V_VH DEFAULT
    LAYER M2 ;
      RECT -0.045 -0.125 0.045 0.125 ;
    LAYER V2 ;
      RECT -0.035 -0.105 0.035 -0.035 ;
      RECT -0.035 0.035 0.035 0.105 ;
    LAYER M3 ;
      RECT -0.065 -0.105 0.065 0.105 ;
END V2_3_S2V_VH

VIA V2_4_VV DEFAULT
    LAYER M2 ;
      RECT -0.045 -0.055 0.045 0.055 ;
    LAYER V2 ;
      RECT -0.035 -0.035 0.035 0.035 ;
    LAYER M3 ;
      RECT -0.045 -0.055 0.045 0.055 ;
END V2_4_VV

VIA V2_4_VH DEFAULT
    LAYER M2 ;
      RECT -0.045 -0.055 0.045 0.055 ;
    LAYER V2 ;
      RECT -0.035 -0.035 0.035 0.035 ;
    LAYER M3 ;
      RECT -0.055 -0.045 0.055 0.045 ;
END V2_4_VH

VIA V2_4_HV DEFAULT
    LAYER M2 ;
      RECT -0.055 -0.045 0.055 0.045 ;
    LAYER V2 ;
      RECT -0.035 -0.035 0.035 0.035 ;
    LAYER M3 ;
      RECT -0.045 -0.055 0.045 0.055 ;
END V2_4_HV

VIA V2_4_HH DEFAULT
    LAYER M2 ;
      RECT -0.055 -0.045 0.055 0.045 ;
    LAYER V2 ;
      RECT -0.035 -0.035 0.035 0.035 ;
    LAYER M3 ;
      RECT -0.055 -0.045 0.055 0.045 ;
END V2_4_HH

VIA V2_4_S2H_VH DEFAULT
    LAYER M2 ;
      RECT -0.115 -0.055 0.115 0.055 ;
    LAYER V2 ;
      RECT -0.105 -0.035 -0.035 0.035 ;
      RECT 0.035 -0.035 0.105 0.035 ;
    LAYER M3 ;
      RECT -0.125 -0.045 0.125 0.045 ;
END V2_4_S2H_VH

VIA V2_4_S2E_VH DEFAULT
    LAYER M2 ;
      RECT -0.045 -0.055 0.185 0.055 ;
    LAYER V2 ;
      RECT -0.035 -0.035 0.035 0.035 ;
      RECT 0.105 -0.035 0.175 0.035 ;
    LAYER M3 ;
      RECT -0.055 -0.045 0.195 0.045 ;
END V2_4_S2E_VH

VIA V2_4_S2N_VH DEFAULT
    LAYER M2 ;
      RECT -0.045 -0.055 0.045 0.195 ;
    LAYER V2 ;
      RECT -0.035 -0.035 0.035 0.035 ;
      RECT -0.035 0.105 0.035 0.175 ;
    LAYER M3 ;
      RECT -0.055 -0.045 0.055 0.185 ;
END V2_4_S2N_VH

VIA V2_4_S2W_VH DEFAULT
    LAYER M2 ;
      RECT -0.185 -0.055 0.045 0.055 ;
    LAYER V2 ;
      RECT -0.175 -0.035 -0.105 0.035 ;
      RECT -0.035 -0.035 0.035 0.035 ;
    LAYER M3 ;
      RECT -0.195 -0.045 0.055 0.045 ;
END V2_4_S2W_VH

VIA V2_4_S2S_VH DEFAULT
    LAYER M2 ;
      RECT -0.045 -0.195 0.045 0.055 ;
    LAYER V2 ;
      RECT -0.035 -0.035 0.035 0.035 ;
      RECT -0.035 -0.175 0.035 -0.105 ;
    LAYER M3 ;
      RECT -0.055 -0.185 0.055 0.045 ;
END V2_4_S2S_VH

VIA V2_4_S2V_VH DEFAULT
    LAYER M2 ;
      RECT -0.045 -0.125 0.045 0.125 ;
    LAYER V2 ;
      RECT -0.035 -0.105 0.035 -0.035 ;
      RECT -0.035 0.035 0.035 0.105 ;
    LAYER M3 ;
      RECT -0.055 -0.115 0.055 0.115 ;
END V2_4_S2V_VH

VIA V2_5_VX DEFAULT
    LAYER M2 ;
      RECT -0.045 -0.055 0.045 0.055 ;
    LAYER V2 ;
      RECT -0.035 -0.035 0.035 0.035 ;
    LAYER M3 ;
      RECT -0.05 -0.05 0.05 0.05 ;
END V2_5_VX

VIA V2_5_HX DEFAULT
    LAYER M2 ;
      RECT -0.055 -0.045 0.055 0.045 ;
    LAYER V2 ;
      RECT -0.035 -0.035 0.035 0.035 ;
    LAYER M3 ;
      RECT -0.05 -0.05 0.05 0.05 ;
END V2_5_HX

VIA V2_5_S2H_VX DEFAULT
    LAYER M2 ;
      RECT -0.115 -0.055 0.115 0.055 ;
    LAYER V2 ;
      RECT -0.105 -0.035 -0.035 0.035 ;
      RECT 0.035 -0.035 0.105 0.035 ;
    LAYER M3 ;
      RECT -0.12 -0.05 0.12 0.05 ;
END V2_5_S2H_VX

VIA V2_5_S2E_VX DEFAULT
    LAYER M2 ;
      RECT -0.045 -0.055 0.185 0.055 ;
    LAYER V2 ;
      RECT -0.035 -0.035 0.035 0.035 ;
      RECT 0.105 -0.035 0.175 0.035 ;
    LAYER M3 ;
      RECT -0.05 -0.05 0.19 0.05 ;
END V2_5_S2E_VX

VIA V2_5_S2N_VX DEFAULT
    LAYER M2 ;
      RECT -0.045 -0.055 0.045 0.195 ;
    LAYER V2 ;
      RECT -0.035 -0.035 0.035 0.035 ;
      RECT -0.035 0.105 0.035 0.175 ;
    LAYER M3 ;
      RECT -0.05 -0.05 0.05 0.19 ;
END V2_5_S2N_VX

VIA V2_5_S2W_VX DEFAULT
    LAYER M2 ;
      RECT -0.185 -0.055 0.045 0.055 ;
    LAYER V2 ;
      RECT -0.175 -0.035 -0.105 0.035 ;
      RECT -0.035 -0.035 0.035 0.035 ;
    LAYER M3 ;
      RECT -0.19 -0.05 0.05 0.05 ;
END V2_5_S2W_VX

VIA V2_5_S2S_VX DEFAULT
    LAYER M2 ;
      RECT -0.045 -0.195 0.045 0.055 ;
    LAYER V2 ;
      RECT -0.035 -0.035 0.035 0.035 ;
      RECT -0.035 -0.175 0.035 -0.105 ;
    LAYER M3 ;
      RECT -0.05 -0.19 0.05 0.05 ;
END V2_5_S2S_VX

VIA V2_5_S2V_VX DEFAULT
    LAYER M2 ;
      RECT -0.045 -0.125 0.045 0.125 ;
    LAYER V2 ;
      RECT -0.035 -0.105 0.035 -0.035 ;
      RECT -0.035 0.035 0.035 0.105 ;
    LAYER M3 ;
      RECT -0.05 -0.12 0.05 0.12 ;
END V2_5_S2V_VX

VIA V2_6_XV DEFAULT
    LAYER M2 ;
      RECT -0.05 -0.05 0.05 0.05 ;
    LAYER V2 ;
      RECT -0.035 -0.035 0.035 0.035 ;
    LAYER M3 ;
      RECT -0.035 -0.065 0.035 0.065 ;
END V2_6_XV

VIA V2_6_XH DEFAULT
    LAYER M2 ;
      RECT -0.05 -0.05 0.05 0.05 ;
    LAYER V2 ;
      RECT -0.035 -0.035 0.035 0.035 ;
    LAYER M3 ;
      RECT -0.065 -0.035 0.065 0.035 ;
END V2_6_XH

VIA V2_6_S2H_XH DEFAULT
    LAYER M2 ;
      RECT -0.12 -0.05 0.12 0.05 ;
    LAYER V2 ;
      RECT -0.105 -0.035 -0.035 0.035 ;
      RECT 0.035 -0.035 0.105 0.035 ;
    LAYER M3 ;
      RECT -0.135 -0.035 0.135 0.035 ;
END V2_6_S2H_XH

VIA V2_6_S2E_XH DEFAULT
    LAYER M2 ;
      RECT -0.05 -0.05 0.19 0.05 ;
    LAYER V2 ;
      RECT -0.035 -0.035 0.035 0.035 ;
      RECT 0.105 -0.035 0.175 0.035 ;
    LAYER M3 ;
      RECT -0.065 -0.035 0.205 0.035 ;
END V2_6_S2E_XH

VIA V2_6_S2N_XH DEFAULT
    LAYER M2 ;
      RECT -0.05 -0.05 0.05 0.19 ;
    LAYER V2 ;
      RECT -0.035 -0.035 0.035 0.035 ;
      RECT -0.035 0.105 0.035 0.175 ;
    LAYER M3 ;
      RECT -0.065 -0.035 0.065 0.175 ;
END V2_6_S2N_XH

VIA V2_6_S2W_XH DEFAULT
    LAYER M2 ;
      RECT -0.19 -0.05 0.05 0.05 ;
    LAYER V2 ;
      RECT -0.175 -0.035 -0.105 0.035 ;
      RECT -0.035 -0.035 0.035 0.035 ;
    LAYER M3 ;
      RECT -0.205 -0.035 0.065 0.035 ;
END V2_6_S2W_XH

VIA V2_6_S2S_XH DEFAULT
    LAYER M2 ;
      RECT -0.05 -0.19 0.05 0.05 ;
    LAYER V2 ;
      RECT -0.035 -0.035 0.035 0.035 ;
      RECT -0.035 -0.175 0.035 -0.105 ;
    LAYER M3 ;
      RECT -0.065 -0.175 0.065 0.035 ;
END V2_6_S2S_XH

VIA V2_6_S2V_XH DEFAULT
    LAYER M2 ;
      RECT -0.05 -0.12 0.05 0.12 ;
    LAYER V2 ;
      RECT -0.035 -0.105 0.035 -0.035 ;
      RECT -0.035 0.035 0.035 0.105 ;
    LAYER M3 ;
      RECT -0.065 -0.105 0.065 0.105 ;
END V2_6_S2V_XH

VIA V2_7_XV DEFAULT
    LAYER M2 ;
      RECT -0.05 -0.05 0.05 0.05 ;
    LAYER V2 ;
      RECT -0.035 -0.035 0.035 0.035 ;
    LAYER M3 ;
      RECT -0.045 -0.055 0.045 0.055 ;
END V2_7_XV

VIA V2_7_XH DEFAULT
    LAYER M2 ;
      RECT -0.05 -0.05 0.05 0.05 ;
    LAYER V2 ;
      RECT -0.035 -0.035 0.035 0.035 ;
    LAYER M3 ;
      RECT -0.055 -0.045 0.055 0.045 ;
END V2_7_XH

VIA V2_7_S2H_XH DEFAULT
    LAYER M2 ;
      RECT -0.12 -0.05 0.12 0.05 ;
    LAYER V2 ;
      RECT -0.105 -0.035 -0.035 0.035 ;
      RECT 0.035 -0.035 0.105 0.035 ;
    LAYER M3 ;
      RECT -0.125 -0.045 0.125 0.045 ;
END V2_7_S2H_XH

VIA V2_7_S2E_XH DEFAULT
    LAYER M2 ;
      RECT -0.05 -0.05 0.19 0.05 ;
    LAYER V2 ;
      RECT -0.035 -0.035 0.035 0.035 ;
      RECT 0.105 -0.035 0.175 0.035 ;
    LAYER M3 ;
      RECT -0.055 -0.045 0.195 0.045 ;
END V2_7_S2E_XH

VIA V2_7_S2N_XH DEFAULT
    LAYER M2 ;
      RECT -0.05 -0.05 0.05 0.19 ;
    LAYER V2 ;
      RECT -0.035 -0.035 0.035 0.035 ;
      RECT -0.035 0.105 0.035 0.175 ;
    LAYER M3 ;
      RECT -0.055 -0.045 0.055 0.185 ;
END V2_7_S2N_XH

VIA V2_7_S2W_XH DEFAULT
    LAYER M2 ;
      RECT -0.19 -0.05 0.05 0.05 ;
    LAYER V2 ;
      RECT -0.175 -0.035 -0.105 0.035 ;
      RECT -0.035 -0.035 0.035 0.035 ;
    LAYER M3 ;
      RECT -0.195 -0.045 0.055 0.045 ;
END V2_7_S2W_XH

VIA V2_7_S2S_XH DEFAULT
    LAYER M2 ;
      RECT -0.05 -0.19 0.05 0.05 ;
    LAYER V2 ;
      RECT -0.035 -0.035 0.035 0.035 ;
      RECT -0.035 -0.175 0.035 -0.105 ;
    LAYER M3 ;
      RECT -0.055 -0.185 0.055 0.045 ;
END V2_7_S2S_XH

VIA V2_7_S2V_XH DEFAULT
    LAYER M2 ;
      RECT -0.05 -0.12 0.05 0.12 ;
    LAYER V2 ;
      RECT -0.035 -0.105 0.035 -0.035 ;
      RECT -0.035 0.035 0.035 0.105 ;
    LAYER M3 ;
      RECT -0.055 -0.115 0.055 0.115 ;
END V2_7_S2V_XH

VIA V2_8_XX DEFAULT
    LAYER M2 ;
      RECT -0.05 -0.05 0.05 0.05 ;
    LAYER V2 ;
      RECT -0.035 -0.035 0.035 0.035 ;
    LAYER M3 ;
      RECT -0.05 -0.05 0.05 0.05 ;
END V2_8_XX

VIA V2_8_S2H_XX DEFAULT
    LAYER M2 ;
      RECT -0.12 -0.05 0.12 0.05 ;
    LAYER V2 ;
      RECT -0.105 -0.035 -0.035 0.035 ;
      RECT 0.035 -0.035 0.105 0.035 ;
    LAYER M3 ;
      RECT -0.12 -0.05 0.12 0.05 ;
END V2_8_S2H_XX

VIA V2_8_S2E_XX DEFAULT
    LAYER M2 ;
      RECT -0.05 -0.05 0.19 0.05 ;
    LAYER V2 ;
      RECT -0.035 -0.035 0.035 0.035 ;
      RECT 0.105 -0.035 0.175 0.035 ;
    LAYER M3 ;
      RECT -0.05 -0.05 0.19 0.05 ;
END V2_8_S2E_XX

VIA V2_8_S2N_XX DEFAULT
    LAYER M2 ;
      RECT -0.05 -0.05 0.05 0.19 ;
    LAYER V2 ;
      RECT -0.035 -0.035 0.035 0.035 ;
      RECT -0.035 0.105 0.035 0.175 ;
    LAYER M3 ;
      RECT -0.05 -0.05 0.05 0.19 ;
END V2_8_S2N_XX

VIA V2_8_S2W_XX DEFAULT
    LAYER M2 ;
      RECT -0.19 -0.05 0.05 0.05 ;
    LAYER V2 ;
      RECT -0.175 -0.035 -0.105 0.035 ;
      RECT -0.035 -0.035 0.035 0.035 ;
    LAYER M3 ;
      RECT -0.19 -0.05 0.05 0.05 ;
END V2_8_S2W_XX

VIA V2_8_S2S_XX DEFAULT
    LAYER M2 ;
      RECT -0.05 -0.19 0.05 0.05 ;
    LAYER V2 ;
      RECT -0.035 -0.035 0.035 0.035 ;
      RECT -0.035 -0.175 0.035 -0.105 ;
    LAYER M3 ;
      RECT -0.05 -0.19 0.05 0.05 ;
END V2_8_S2S_XX

VIA V2_8_S2V_XX DEFAULT
    LAYER M2 ;
      RECT -0.05 -0.12 0.05 0.12 ;
    LAYER V2 ;
      RECT -0.035 -0.105 0.035 -0.035 ;
      RECT -0.035 0.035 0.035 0.105 ;
    LAYER M3 ;
      RECT -0.05 -0.12 0.05 0.12 ;
END V2_8_S2V_XX

VIA V3_0_VV DEFAULT
    LAYER M3 ;
      RECT -0.035 -0.065 0.035 0.065 ;
    LAYER V3 ;
      RECT -0.035 -0.035 0.035 0.035 ;
    LAYER M4 ;
      RECT -0.035 -0.065 0.035 0.065 ;
END V3_0_VV

VIA V3_0_VH DEFAULT
    LAYER M3 ;
      RECT -0.035 -0.065 0.035 0.065 ;
    LAYER V3 ;
      RECT -0.035 -0.035 0.035 0.035 ;
    LAYER M4 ;
      RECT -0.065 -0.035 0.065 0.035 ;
END V3_0_VH

VIA V3_0_HV DEFAULT
    LAYER M3 ;
      RECT -0.065 -0.035 0.065 0.035 ;
    LAYER V3 ;
      RECT -0.035 -0.035 0.035 0.035 ;
    LAYER M4 ;
      RECT -0.035 -0.065 0.035 0.065 ;
END V3_0_HV

VIA V3_0_HH DEFAULT
    LAYER M3 ;
      RECT -0.065 -0.035 0.065 0.035 ;
    LAYER V3 ;
      RECT -0.035 -0.035 0.035 0.035 ;
    LAYER M4 ;
      RECT -0.065 -0.035 0.065 0.035 ;
END V3_0_HH

VIA V3_0_S2H_VH DEFAULT
    LAYER M3 ;
      RECT -0.105 -0.065 0.105 0.065 ;
    LAYER V3 ;
      RECT -0.105 -0.035 -0.035 0.035 ;
      RECT 0.035 -0.035 0.105 0.035 ;
    LAYER M4 ;
      RECT -0.135 -0.035 0.135 0.035 ;
END V3_0_S2H_VH

VIA V3_0_S2E_VH DEFAULT
    LAYER M3 ;
      RECT -0.035 -0.065 0.175 0.065 ;
    LAYER V3 ;
      RECT -0.035 -0.035 0.035 0.035 ;
      RECT 0.105 -0.035 0.175 0.035 ;
    LAYER M4 ;
      RECT -0.065 -0.035 0.205 0.035 ;
END V3_0_S2E_VH

VIA V3_0_S2N_VH DEFAULT
    LAYER M3 ;
      RECT -0.035 -0.065 0.035 0.205 ;
    LAYER V3 ;
      RECT -0.035 -0.035 0.035 0.035 ;
      RECT -0.035 0.105 0.035 0.175 ;
    LAYER M4 ;
      RECT -0.065 -0.035 0.065 0.175 ;
END V3_0_S2N_VH

VIA V3_0_S2W_VH DEFAULT
    LAYER M3 ;
      RECT -0.175 -0.065 0.035 0.065 ;
    LAYER V3 ;
      RECT -0.175 -0.035 -0.105 0.035 ;
      RECT -0.035 -0.035 0.035 0.035 ;
    LAYER M4 ;
      RECT -0.205 -0.035 0.065 0.035 ;
END V3_0_S2W_VH

VIA V3_0_S2S_VH DEFAULT
    LAYER M3 ;
      RECT -0.035 -0.205 0.035 0.065 ;
    LAYER V3 ;
      RECT -0.035 -0.035 0.035 0.035 ;
      RECT -0.035 -0.175 0.035 -0.105 ;
    LAYER M4 ;
      RECT -0.065 -0.175 0.065 0.035 ;
END V3_0_S2S_VH

VIA V3_0_S2V_VH DEFAULT
    LAYER M3 ;
      RECT -0.035 -0.135 0.035 0.135 ;
    LAYER V3 ;
      RECT -0.035 -0.105 0.035 -0.035 ;
      RECT -0.035 0.035 0.035 0.105 ;
    LAYER M4 ;
      RECT -0.065 -0.105 0.065 0.105 ;
END V3_0_S2V_VH

VIA V3_1_VV DEFAULT
    LAYER M3 ;
      RECT -0.035 -0.065 0.035 0.065 ;
    LAYER V3 ;
      RECT -0.035 -0.035 0.035 0.035 ;
    LAYER M4 ;
      RECT -0.045 -0.055 0.045 0.055 ;
END V3_1_VV

VIA V3_1_VH DEFAULT
    LAYER M3 ;
      RECT -0.035 -0.065 0.035 0.065 ;
    LAYER V3 ;
      RECT -0.035 -0.035 0.035 0.035 ;
    LAYER M4 ;
      RECT -0.055 -0.045 0.055 0.045 ;
END V3_1_VH

VIA V3_1_HV DEFAULT
    LAYER M3 ;
      RECT -0.065 -0.035 0.065 0.035 ;
    LAYER V3 ;
      RECT -0.035 -0.035 0.035 0.035 ;
    LAYER M4 ;
      RECT -0.045 -0.055 0.045 0.055 ;
END V3_1_HV

VIA V3_1_HH DEFAULT
    LAYER M3 ;
      RECT -0.065 -0.035 0.065 0.035 ;
    LAYER V3 ;
      RECT -0.035 -0.035 0.035 0.035 ;
    LAYER M4 ;
      RECT -0.055 -0.045 0.055 0.045 ;
END V3_1_HH

VIA V3_1_S2H_VH DEFAULT
    LAYER M3 ;
      RECT -0.105 -0.065 0.105 0.065 ;
    LAYER V3 ;
      RECT -0.105 -0.035 -0.035 0.035 ;
      RECT 0.035 -0.035 0.105 0.035 ;
    LAYER M4 ;
      RECT -0.125 -0.045 0.125 0.045 ;
END V3_1_S2H_VH

VIA V3_1_S2E_VH DEFAULT
    LAYER M3 ;
      RECT -0.035 -0.065 0.175 0.065 ;
    LAYER V3 ;
      RECT -0.035 -0.035 0.035 0.035 ;
      RECT 0.105 -0.035 0.175 0.035 ;
    LAYER M4 ;
      RECT -0.055 -0.045 0.195 0.045 ;
END V3_1_S2E_VH

VIA V3_1_S2N_VH DEFAULT
    LAYER M3 ;
      RECT -0.035 -0.065 0.035 0.205 ;
    LAYER V3 ;
      RECT -0.035 -0.035 0.035 0.035 ;
      RECT -0.035 0.105 0.035 0.175 ;
    LAYER M4 ;
      RECT -0.055 -0.045 0.055 0.185 ;
END V3_1_S2N_VH

VIA V3_1_S2W_VH DEFAULT
    LAYER M3 ;
      RECT -0.175 -0.065 0.035 0.065 ;
    LAYER V3 ;
      RECT -0.175 -0.035 -0.105 0.035 ;
      RECT -0.035 -0.035 0.035 0.035 ;
    LAYER M4 ;
      RECT -0.195 -0.045 0.055 0.045 ;
END V3_1_S2W_VH

VIA V3_1_S2S_VH DEFAULT
    LAYER M3 ;
      RECT -0.035 -0.205 0.035 0.065 ;
    LAYER V3 ;
      RECT -0.035 -0.035 0.035 0.035 ;
      RECT -0.035 -0.175 0.035 -0.105 ;
    LAYER M4 ;
      RECT -0.055 -0.185 0.055 0.045 ;
END V3_1_S2S_VH

VIA V3_1_S2V_VH DEFAULT
    LAYER M3 ;
      RECT -0.035 -0.135 0.035 0.135 ;
    LAYER V3 ;
      RECT -0.035 -0.105 0.035 -0.035 ;
      RECT -0.035 0.035 0.035 0.105 ;
    LAYER M4 ;
      RECT -0.055 -0.115 0.055 0.115 ;
END V3_1_S2V_VH

VIA V3_2_VX DEFAULT
    LAYER M3 ;
      RECT -0.035 -0.065 0.035 0.065 ;
    LAYER V3 ;
      RECT -0.035 -0.035 0.035 0.035 ;
    LAYER M4 ;
      RECT -0.05 -0.05 0.05 0.05 ;
END V3_2_VX

VIA V3_2_HX DEFAULT
    LAYER M3 ;
      RECT -0.065 -0.035 0.065 0.035 ;
    LAYER V3 ;
      RECT -0.035 -0.035 0.035 0.035 ;
    LAYER M4 ;
      RECT -0.05 -0.05 0.05 0.05 ;
END V3_2_HX

VIA V3_2_S2H_VX DEFAULT
    LAYER M3 ;
      RECT -0.105 -0.065 0.105 0.065 ;
    LAYER V3 ;
      RECT -0.105 -0.035 -0.035 0.035 ;
      RECT 0.035 -0.035 0.105 0.035 ;
    LAYER M4 ;
      RECT -0.12 -0.05 0.12 0.05 ;
END V3_2_S2H_VX

VIA V3_2_S2E_VX DEFAULT
    LAYER M3 ;
      RECT -0.035 -0.065 0.175 0.065 ;
    LAYER V3 ;
      RECT -0.035 -0.035 0.035 0.035 ;
      RECT 0.105 -0.035 0.175 0.035 ;
    LAYER M4 ;
      RECT -0.05 -0.05 0.19 0.05 ;
END V3_2_S2E_VX

VIA V3_2_S2N_VX DEFAULT
    LAYER M3 ;
      RECT -0.035 -0.065 0.035 0.205 ;
    LAYER V3 ;
      RECT -0.035 -0.035 0.035 0.035 ;
      RECT -0.035 0.105 0.035 0.175 ;
    LAYER M4 ;
      RECT -0.05 -0.05 0.05 0.19 ;
END V3_2_S2N_VX

VIA V3_2_S2W_VX DEFAULT
    LAYER M3 ;
      RECT -0.175 -0.065 0.035 0.065 ;
    LAYER V3 ;
      RECT -0.175 -0.035 -0.105 0.035 ;
      RECT -0.035 -0.035 0.035 0.035 ;
    LAYER M4 ;
      RECT -0.19 -0.05 0.05 0.05 ;
END V3_2_S2W_VX

VIA V3_2_S2S_VX DEFAULT
    LAYER M3 ;
      RECT -0.035 -0.205 0.035 0.065 ;
    LAYER V3 ;
      RECT -0.035 -0.035 0.035 0.035 ;
      RECT -0.035 -0.175 0.035 -0.105 ;
    LAYER M4 ;
      RECT -0.05 -0.19 0.05 0.05 ;
END V3_2_S2S_VX

VIA V3_2_S2V_VX DEFAULT
    LAYER M3 ;
      RECT -0.035 -0.135 0.035 0.135 ;
    LAYER V3 ;
      RECT -0.035 -0.105 0.035 -0.035 ;
      RECT -0.035 0.035 0.035 0.105 ;
    LAYER M4 ;
      RECT -0.05 -0.12 0.05 0.12 ;
END V3_2_S2V_VX

VIA V3_3_VV DEFAULT
    LAYER M3 ;
      RECT -0.045 -0.055 0.045 0.055 ;
    LAYER V3 ;
      RECT -0.035 -0.035 0.035 0.035 ;
    LAYER M4 ;
      RECT -0.035 -0.065 0.035 0.065 ;
END V3_3_VV

VIA V3_3_VH DEFAULT
    LAYER M3 ;
      RECT -0.045 -0.055 0.045 0.055 ;
    LAYER V3 ;
      RECT -0.035 -0.035 0.035 0.035 ;
    LAYER M4 ;
      RECT -0.065 -0.035 0.065 0.035 ;
END V3_3_VH

VIA V3_3_HV DEFAULT
    LAYER M3 ;
      RECT -0.055 -0.045 0.055 0.045 ;
    LAYER V3 ;
      RECT -0.035 -0.035 0.035 0.035 ;
    LAYER M4 ;
      RECT -0.035 -0.065 0.035 0.065 ;
END V3_3_HV

VIA V3_3_HH DEFAULT
    LAYER M3 ;
      RECT -0.055 -0.045 0.055 0.045 ;
    LAYER V3 ;
      RECT -0.035 -0.035 0.035 0.035 ;
    LAYER M4 ;
      RECT -0.065 -0.035 0.065 0.035 ;
END V3_3_HH

VIA V3_3_S2H_VH DEFAULT
    LAYER M3 ;
      RECT -0.115 -0.055 0.115 0.055 ;
    LAYER V3 ;
      RECT -0.105 -0.035 -0.035 0.035 ;
      RECT 0.035 -0.035 0.105 0.035 ;
    LAYER M4 ;
      RECT -0.135 -0.035 0.135 0.035 ;
END V3_3_S2H_VH

VIA V3_3_S2E_VH DEFAULT
    LAYER M3 ;
      RECT -0.045 -0.055 0.185 0.055 ;
    LAYER V3 ;
      RECT -0.035 -0.035 0.035 0.035 ;
      RECT 0.105 -0.035 0.175 0.035 ;
    LAYER M4 ;
      RECT -0.065 -0.035 0.205 0.035 ;
END V3_3_S2E_VH

VIA V3_3_S2N_VH DEFAULT
    LAYER M3 ;
      RECT -0.045 -0.055 0.045 0.195 ;
    LAYER V3 ;
      RECT -0.035 -0.035 0.035 0.035 ;
      RECT -0.035 0.105 0.035 0.175 ;
    LAYER M4 ;
      RECT -0.065 -0.035 0.065 0.175 ;
END V3_3_S2N_VH

VIA V3_3_S2W_VH DEFAULT
    LAYER M3 ;
      RECT -0.185 -0.055 0.045 0.055 ;
    LAYER V3 ;
      RECT -0.175 -0.035 -0.105 0.035 ;
      RECT -0.035 -0.035 0.035 0.035 ;
    LAYER M4 ;
      RECT -0.205 -0.035 0.065 0.035 ;
END V3_3_S2W_VH

VIA V3_3_S2S_VH DEFAULT
    LAYER M3 ;
      RECT -0.045 -0.195 0.045 0.055 ;
    LAYER V3 ;
      RECT -0.035 -0.035 0.035 0.035 ;
      RECT -0.035 -0.175 0.035 -0.105 ;
    LAYER M4 ;
      RECT -0.065 -0.175 0.065 0.035 ;
END V3_3_S2S_VH

VIA V3_3_S2V_VH DEFAULT
    LAYER M3 ;
      RECT -0.045 -0.125 0.045 0.125 ;
    LAYER V3 ;
      RECT -0.035 -0.105 0.035 -0.035 ;
      RECT -0.035 0.035 0.035 0.105 ;
    LAYER M4 ;
      RECT -0.065 -0.105 0.065 0.105 ;
END V3_3_S2V_VH

VIA V3_4_VV DEFAULT
    LAYER M3 ;
      RECT -0.045 -0.055 0.045 0.055 ;
    LAYER V3 ;
      RECT -0.035 -0.035 0.035 0.035 ;
    LAYER M4 ;
      RECT -0.045 -0.055 0.045 0.055 ;
END V3_4_VV

VIA V3_4_VH DEFAULT
    LAYER M3 ;
      RECT -0.045 -0.055 0.045 0.055 ;
    LAYER V3 ;
      RECT -0.035 -0.035 0.035 0.035 ;
    LAYER M4 ;
      RECT -0.055 -0.045 0.055 0.045 ;
END V3_4_VH

VIA V3_4_HV DEFAULT
    LAYER M3 ;
      RECT -0.055 -0.045 0.055 0.045 ;
    LAYER V3 ;
      RECT -0.035 -0.035 0.035 0.035 ;
    LAYER M4 ;
      RECT -0.045 -0.055 0.045 0.055 ;
END V3_4_HV

VIA V3_4_HH DEFAULT
    LAYER M3 ;
      RECT -0.055 -0.045 0.055 0.045 ;
    LAYER V3 ;
      RECT -0.035 -0.035 0.035 0.035 ;
    LAYER M4 ;
      RECT -0.055 -0.045 0.055 0.045 ;
END V3_4_HH

VIA V3_4_S2H_VH DEFAULT
    LAYER M3 ;
      RECT -0.115 -0.055 0.115 0.055 ;
    LAYER V3 ;
      RECT -0.105 -0.035 -0.035 0.035 ;
      RECT 0.035 -0.035 0.105 0.035 ;
    LAYER M4 ;
      RECT -0.125 -0.045 0.125 0.045 ;
END V3_4_S2H_VH

VIA V3_4_S2E_VH DEFAULT
    LAYER M3 ;
      RECT -0.045 -0.055 0.185 0.055 ;
    LAYER V3 ;
      RECT -0.035 -0.035 0.035 0.035 ;
      RECT 0.105 -0.035 0.175 0.035 ;
    LAYER M4 ;
      RECT -0.055 -0.045 0.195 0.045 ;
END V3_4_S2E_VH

VIA V3_4_S2N_VH DEFAULT
    LAYER M3 ;
      RECT -0.045 -0.055 0.045 0.195 ;
    LAYER V3 ;
      RECT -0.035 -0.035 0.035 0.035 ;
      RECT -0.035 0.105 0.035 0.175 ;
    LAYER M4 ;
      RECT -0.055 -0.045 0.055 0.185 ;
END V3_4_S2N_VH

VIA V3_4_S2W_VH DEFAULT
    LAYER M3 ;
      RECT -0.185 -0.055 0.045 0.055 ;
    LAYER V3 ;
      RECT -0.175 -0.035 -0.105 0.035 ;
      RECT -0.035 -0.035 0.035 0.035 ;
    LAYER M4 ;
      RECT -0.195 -0.045 0.055 0.045 ;
END V3_4_S2W_VH

VIA V3_4_S2S_VH DEFAULT
    LAYER M3 ;
      RECT -0.045 -0.195 0.045 0.055 ;
    LAYER V3 ;
      RECT -0.035 -0.035 0.035 0.035 ;
      RECT -0.035 -0.175 0.035 -0.105 ;
    LAYER M4 ;
      RECT -0.055 -0.185 0.055 0.045 ;
END V3_4_S2S_VH

VIA V3_4_S2V_VH DEFAULT
    LAYER M3 ;
      RECT -0.045 -0.125 0.045 0.125 ;
    LAYER V3 ;
      RECT -0.035 -0.105 0.035 -0.035 ;
      RECT -0.035 0.035 0.035 0.105 ;
    LAYER M4 ;
      RECT -0.055 -0.115 0.055 0.115 ;
END V3_4_S2V_VH

VIA V3_5_VX DEFAULT
    LAYER M3 ;
      RECT -0.045 -0.055 0.045 0.055 ;
    LAYER V3 ;
      RECT -0.035 -0.035 0.035 0.035 ;
    LAYER M4 ;
      RECT -0.05 -0.05 0.05 0.05 ;
END V3_5_VX

VIA V3_5_HX DEFAULT
    LAYER M3 ;
      RECT -0.055 -0.045 0.055 0.045 ;
    LAYER V3 ;
      RECT -0.035 -0.035 0.035 0.035 ;
    LAYER M4 ;
      RECT -0.05 -0.05 0.05 0.05 ;
END V3_5_HX

VIA V3_5_S2H_VX DEFAULT
    LAYER M3 ;
      RECT -0.115 -0.055 0.115 0.055 ;
    LAYER V3 ;
      RECT -0.105 -0.035 -0.035 0.035 ;
      RECT 0.035 -0.035 0.105 0.035 ;
    LAYER M4 ;
      RECT -0.12 -0.05 0.12 0.05 ;
END V3_5_S2H_VX

VIA V3_5_S2E_VX DEFAULT
    LAYER M3 ;
      RECT -0.045 -0.055 0.185 0.055 ;
    LAYER V3 ;
      RECT -0.035 -0.035 0.035 0.035 ;
      RECT 0.105 -0.035 0.175 0.035 ;
    LAYER M4 ;
      RECT -0.05 -0.05 0.19 0.05 ;
END V3_5_S2E_VX

VIA V3_5_S2N_VX DEFAULT
    LAYER M3 ;
      RECT -0.045 -0.055 0.045 0.195 ;
    LAYER V3 ;
      RECT -0.035 -0.035 0.035 0.035 ;
      RECT -0.035 0.105 0.035 0.175 ;
    LAYER M4 ;
      RECT -0.05 -0.05 0.05 0.19 ;
END V3_5_S2N_VX

VIA V3_5_S2W_VX DEFAULT
    LAYER M3 ;
      RECT -0.185 -0.055 0.045 0.055 ;
    LAYER V3 ;
      RECT -0.175 -0.035 -0.105 0.035 ;
      RECT -0.035 -0.035 0.035 0.035 ;
    LAYER M4 ;
      RECT -0.19 -0.05 0.05 0.05 ;
END V3_5_S2W_VX

VIA V3_5_S2S_VX DEFAULT
    LAYER M3 ;
      RECT -0.045 -0.195 0.045 0.055 ;
    LAYER V3 ;
      RECT -0.035 -0.035 0.035 0.035 ;
      RECT -0.035 -0.175 0.035 -0.105 ;
    LAYER M4 ;
      RECT -0.05 -0.19 0.05 0.05 ;
END V3_5_S2S_VX

VIA V3_5_S2V_VX DEFAULT
    LAYER M3 ;
      RECT -0.045 -0.125 0.045 0.125 ;
    LAYER V3 ;
      RECT -0.035 -0.105 0.035 -0.035 ;
      RECT -0.035 0.035 0.035 0.105 ;
    LAYER M4 ;
      RECT -0.05 -0.12 0.05 0.12 ;
END V3_5_S2V_VX

VIA V3_6_XV DEFAULT
    LAYER M3 ;
      RECT -0.05 -0.05 0.05 0.05 ;
    LAYER V3 ;
      RECT -0.035 -0.035 0.035 0.035 ;
    LAYER M4 ;
      RECT -0.035 -0.065 0.035 0.065 ;
END V3_6_XV

VIA V3_6_XH DEFAULT
    LAYER M3 ;
      RECT -0.05 -0.05 0.05 0.05 ;
    LAYER V3 ;
      RECT -0.035 -0.035 0.035 0.035 ;
    LAYER M4 ;
      RECT -0.065 -0.035 0.065 0.035 ;
END V3_6_XH

VIA V3_6_S2H_XH DEFAULT
    LAYER M3 ;
      RECT -0.12 -0.05 0.12 0.05 ;
    LAYER V3 ;
      RECT -0.105 -0.035 -0.035 0.035 ;
      RECT 0.035 -0.035 0.105 0.035 ;
    LAYER M4 ;
      RECT -0.135 -0.035 0.135 0.035 ;
END V3_6_S2H_XH

VIA V3_6_S2E_XH DEFAULT
    LAYER M3 ;
      RECT -0.05 -0.05 0.19 0.05 ;
    LAYER V3 ;
      RECT -0.035 -0.035 0.035 0.035 ;
      RECT 0.105 -0.035 0.175 0.035 ;
    LAYER M4 ;
      RECT -0.065 -0.035 0.205 0.035 ;
END V3_6_S2E_XH

VIA V3_6_S2N_XH DEFAULT
    LAYER M3 ;
      RECT -0.05 -0.05 0.05 0.19 ;
    LAYER V3 ;
      RECT -0.035 -0.035 0.035 0.035 ;
      RECT -0.035 0.105 0.035 0.175 ;
    LAYER M4 ;
      RECT -0.065 -0.035 0.065 0.175 ;
END V3_6_S2N_XH

VIA V3_6_S2W_XH DEFAULT
    LAYER M3 ;
      RECT -0.19 -0.05 0.05 0.05 ;
    LAYER V3 ;
      RECT -0.175 -0.035 -0.105 0.035 ;
      RECT -0.035 -0.035 0.035 0.035 ;
    LAYER M4 ;
      RECT -0.205 -0.035 0.065 0.035 ;
END V3_6_S2W_XH

VIA V3_6_S2S_XH DEFAULT
    LAYER M3 ;
      RECT -0.05 -0.19 0.05 0.05 ;
    LAYER V3 ;
      RECT -0.035 -0.035 0.035 0.035 ;
      RECT -0.035 -0.175 0.035 -0.105 ;
    LAYER M4 ;
      RECT -0.065 -0.175 0.065 0.035 ;
END V3_6_S2S_XH

VIA V3_6_S2V_XH DEFAULT
    LAYER M3 ;
      RECT -0.05 -0.12 0.05 0.12 ;
    LAYER V3 ;
      RECT -0.035 -0.105 0.035 -0.035 ;
      RECT -0.035 0.035 0.035 0.105 ;
    LAYER M4 ;
      RECT -0.065 -0.105 0.065 0.105 ;
END V3_6_S2V_XH

VIA V3_7_XV DEFAULT
    LAYER M3 ;
      RECT -0.05 -0.05 0.05 0.05 ;
    LAYER V3 ;
      RECT -0.035 -0.035 0.035 0.035 ;
    LAYER M4 ;
      RECT -0.045 -0.055 0.045 0.055 ;
END V3_7_XV

VIA V3_7_XH DEFAULT
    LAYER M3 ;
      RECT -0.05 -0.05 0.05 0.05 ;
    LAYER V3 ;
      RECT -0.035 -0.035 0.035 0.035 ;
    LAYER M4 ;
      RECT -0.055 -0.045 0.055 0.045 ;
END V3_7_XH

VIA V3_7_S2H_XH DEFAULT
    LAYER M3 ;
      RECT -0.12 -0.05 0.12 0.05 ;
    LAYER V3 ;
      RECT -0.105 -0.035 -0.035 0.035 ;
      RECT 0.035 -0.035 0.105 0.035 ;
    LAYER M4 ;
      RECT -0.125 -0.045 0.125 0.045 ;
END V3_7_S2H_XH

VIA V3_7_S2E_XH DEFAULT
    LAYER M3 ;
      RECT -0.05 -0.05 0.19 0.05 ;
    LAYER V3 ;
      RECT -0.035 -0.035 0.035 0.035 ;
      RECT 0.105 -0.035 0.175 0.035 ;
    LAYER M4 ;
      RECT -0.055 -0.045 0.195 0.045 ;
END V3_7_S2E_XH

VIA V3_7_S2N_XH DEFAULT
    LAYER M3 ;
      RECT -0.05 -0.05 0.05 0.19 ;
    LAYER V3 ;
      RECT -0.035 -0.035 0.035 0.035 ;
      RECT -0.035 0.105 0.035 0.175 ;
    LAYER M4 ;
      RECT -0.055 -0.045 0.055 0.185 ;
END V3_7_S2N_XH

VIA V3_7_S2W_XH DEFAULT
    LAYER M3 ;
      RECT -0.19 -0.05 0.05 0.05 ;
    LAYER V3 ;
      RECT -0.175 -0.035 -0.105 0.035 ;
      RECT -0.035 -0.035 0.035 0.035 ;
    LAYER M4 ;
      RECT -0.195 -0.045 0.055 0.045 ;
END V3_7_S2W_XH

VIA V3_7_S2S_XH DEFAULT
    LAYER M3 ;
      RECT -0.05 -0.19 0.05 0.05 ;
    LAYER V3 ;
      RECT -0.035 -0.035 0.035 0.035 ;
      RECT -0.035 -0.175 0.035 -0.105 ;
    LAYER M4 ;
      RECT -0.055 -0.185 0.055 0.045 ;
END V3_7_S2S_XH

VIA V3_7_S2V_XH DEFAULT
    LAYER M3 ;
      RECT -0.05 -0.12 0.05 0.12 ;
    LAYER V3 ;
      RECT -0.035 -0.105 0.035 -0.035 ;
      RECT -0.035 0.035 0.035 0.105 ;
    LAYER M4 ;
      RECT -0.055 -0.115 0.055 0.115 ;
END V3_7_S2V_XH

VIA V3_8_XX DEFAULT
    LAYER M3 ;
      RECT -0.05 -0.05 0.05 0.05 ;
    LAYER V3 ;
      RECT -0.035 -0.035 0.035 0.035 ;
    LAYER M4 ;
      RECT -0.05 -0.05 0.05 0.05 ;
END V3_8_XX

VIA V3_8_S2H_XX DEFAULT
    LAYER M3 ;
      RECT -0.12 -0.05 0.12 0.05 ;
    LAYER V3 ;
      RECT -0.105 -0.035 -0.035 0.035 ;
      RECT 0.035 -0.035 0.105 0.035 ;
    LAYER M4 ;
      RECT -0.12 -0.05 0.12 0.05 ;
END V3_8_S2H_XX

VIA V3_8_S2E_XX DEFAULT
    LAYER M3 ;
      RECT -0.05 -0.05 0.19 0.05 ;
    LAYER V3 ;
      RECT -0.035 -0.035 0.035 0.035 ;
      RECT 0.105 -0.035 0.175 0.035 ;
    LAYER M4 ;
      RECT -0.05 -0.05 0.19 0.05 ;
END V3_8_S2E_XX

VIA V3_8_S2N_XX DEFAULT
    LAYER M3 ;
      RECT -0.05 -0.05 0.05 0.19 ;
    LAYER V3 ;
      RECT -0.035 -0.035 0.035 0.035 ;
      RECT -0.035 0.105 0.035 0.175 ;
    LAYER M4 ;
      RECT -0.05 -0.05 0.05 0.19 ;
END V3_8_S2N_XX

VIA V3_8_S2W_XX DEFAULT
    LAYER M3 ;
      RECT -0.19 -0.05 0.05 0.05 ;
    LAYER V3 ;
      RECT -0.175 -0.035 -0.105 0.035 ;
      RECT -0.035 -0.035 0.035 0.035 ;
    LAYER M4 ;
      RECT -0.19 -0.05 0.05 0.05 ;
END V3_8_S2W_XX

VIA V3_8_S2S_XX DEFAULT
    LAYER M3 ;
      RECT -0.05 -0.19 0.05 0.05 ;
    LAYER V3 ;
      RECT -0.035 -0.035 0.035 0.035 ;
      RECT -0.035 -0.175 0.035 -0.105 ;
    LAYER M4 ;
      RECT -0.05 -0.19 0.05 0.05 ;
END V3_8_S2S_XX

VIA V3_8_S2V_XX DEFAULT
    LAYER M3 ;
      RECT -0.05 -0.12 0.05 0.12 ;
    LAYER V3 ;
      RECT -0.035 -0.105 0.035 -0.035 ;
      RECT -0.035 0.035 0.035 0.105 ;
    LAYER M4 ;
      RECT -0.05 -0.12 0.05 0.12 ;
END V3_8_S2V_XX

VIA V4_0_VV DEFAULT
    LAYER M4 ;
      RECT -0.035 -0.065 0.035 0.065 ;
    LAYER V4 ;
      RECT -0.035 -0.035 0.035 0.035 ;
    LAYER M5 ;
      RECT -0.035 -0.065 0.035 0.065 ;
END V4_0_VV

VIA V4_0_VH DEFAULT
    LAYER M4 ;
      RECT -0.035 -0.065 0.035 0.065 ;
    LAYER V4 ;
      RECT -0.035 -0.035 0.035 0.035 ;
    LAYER M5 ;
      RECT -0.065 -0.035 0.065 0.035 ;
END V4_0_VH

VIA V4_0_HV DEFAULT
    LAYER M4 ;
      RECT -0.065 -0.035 0.065 0.035 ;
    LAYER V4 ;
      RECT -0.035 -0.035 0.035 0.035 ;
    LAYER M5 ;
      RECT -0.035 -0.065 0.035 0.065 ;
END V4_0_HV

VIA V4_0_HH DEFAULT
    LAYER M4 ;
      RECT -0.065 -0.035 0.065 0.035 ;
    LAYER V4 ;
      RECT -0.035 -0.035 0.035 0.035 ;
    LAYER M5 ;
      RECT -0.065 -0.035 0.065 0.035 ;
END V4_0_HH

VIA V4_0_S2H_VH DEFAULT
    LAYER M4 ;
      RECT -0.105 -0.065 0.105 0.065 ;
    LAYER V4 ;
      RECT -0.105 -0.035 -0.035 0.035 ;
      RECT 0.035 -0.035 0.105 0.035 ;
    LAYER M5 ;
      RECT -0.135 -0.035 0.135 0.035 ;
END V4_0_S2H_VH

VIA V4_0_S2E_VH DEFAULT
    LAYER M4 ;
      RECT -0.035 -0.065 0.175 0.065 ;
    LAYER V4 ;
      RECT -0.035 -0.035 0.035 0.035 ;
      RECT 0.105 -0.035 0.175 0.035 ;
    LAYER M5 ;
      RECT -0.065 -0.035 0.205 0.035 ;
END V4_0_S2E_VH

VIA V4_0_S2N_VH DEFAULT
    LAYER M4 ;
      RECT -0.035 -0.065 0.035 0.205 ;
    LAYER V4 ;
      RECT -0.035 -0.035 0.035 0.035 ;
      RECT -0.035 0.105 0.035 0.175 ;
    LAYER M5 ;
      RECT -0.065 -0.035 0.065 0.175 ;
END V4_0_S2N_VH

VIA V4_0_S2W_VH DEFAULT
    LAYER M4 ;
      RECT -0.175 -0.065 0.035 0.065 ;
    LAYER V4 ;
      RECT -0.175 -0.035 -0.105 0.035 ;
      RECT -0.035 -0.035 0.035 0.035 ;
    LAYER M5 ;
      RECT -0.205 -0.035 0.065 0.035 ;
END V4_0_S2W_VH

VIA V4_0_S2S_VH DEFAULT
    LAYER M4 ;
      RECT -0.035 -0.205 0.035 0.065 ;
    LAYER V4 ;
      RECT -0.035 -0.035 0.035 0.035 ;
      RECT -0.035 -0.175 0.035 -0.105 ;
    LAYER M5 ;
      RECT -0.065 -0.175 0.065 0.035 ;
END V4_0_S2S_VH

VIA V4_0_S2V_VH DEFAULT
    LAYER M4 ;
      RECT -0.035 -0.135 0.035 0.135 ;
    LAYER V4 ;
      RECT -0.035 -0.105 0.035 -0.035 ;
      RECT -0.035 0.035 0.035 0.105 ;
    LAYER M5 ;
      RECT -0.065 -0.105 0.065 0.105 ;
END V4_0_S2V_VH

VIA V4_1_VV DEFAULT
    LAYER M4 ;
      RECT -0.035 -0.065 0.035 0.065 ;
    LAYER V4 ;
      RECT -0.035 -0.035 0.035 0.035 ;
    LAYER M5 ;
      RECT -0.045 -0.055 0.045 0.055 ;
END V4_1_VV

VIA V4_1_VH DEFAULT
    LAYER M4 ;
      RECT -0.035 -0.065 0.035 0.065 ;
    LAYER V4 ;
      RECT -0.035 -0.035 0.035 0.035 ;
    LAYER M5 ;
      RECT -0.055 -0.045 0.055 0.045 ;
END V4_1_VH

VIA V4_1_HV DEFAULT
    LAYER M4 ;
      RECT -0.065 -0.035 0.065 0.035 ;
    LAYER V4 ;
      RECT -0.035 -0.035 0.035 0.035 ;
    LAYER M5 ;
      RECT -0.045 -0.055 0.045 0.055 ;
END V4_1_HV

VIA V4_1_HH DEFAULT
    LAYER M4 ;
      RECT -0.065 -0.035 0.065 0.035 ;
    LAYER V4 ;
      RECT -0.035 -0.035 0.035 0.035 ;
    LAYER M5 ;
      RECT -0.055 -0.045 0.055 0.045 ;
END V4_1_HH

VIA V4_1_S2H_VH DEFAULT
    LAYER M4 ;
      RECT -0.105 -0.065 0.105 0.065 ;
    LAYER V4 ;
      RECT -0.105 -0.035 -0.035 0.035 ;
      RECT 0.035 -0.035 0.105 0.035 ;
    LAYER M5 ;
      RECT -0.125 -0.045 0.125 0.045 ;
END V4_1_S2H_VH

VIA V4_1_S2E_VH DEFAULT
    LAYER M4 ;
      RECT -0.035 -0.065 0.175 0.065 ;
    LAYER V4 ;
      RECT -0.035 -0.035 0.035 0.035 ;
      RECT 0.105 -0.035 0.175 0.035 ;
    LAYER M5 ;
      RECT -0.055 -0.045 0.195 0.045 ;
END V4_1_S2E_VH

VIA V4_1_S2N_VH DEFAULT
    LAYER M4 ;
      RECT -0.035 -0.065 0.035 0.205 ;
    LAYER V4 ;
      RECT -0.035 -0.035 0.035 0.035 ;
      RECT -0.035 0.105 0.035 0.175 ;
    LAYER M5 ;
      RECT -0.055 -0.045 0.055 0.185 ;
END V4_1_S2N_VH

VIA V4_1_S2W_VH DEFAULT
    LAYER M4 ;
      RECT -0.175 -0.065 0.035 0.065 ;
    LAYER V4 ;
      RECT -0.175 -0.035 -0.105 0.035 ;
      RECT -0.035 -0.035 0.035 0.035 ;
    LAYER M5 ;
      RECT -0.195 -0.045 0.055 0.045 ;
END V4_1_S2W_VH

VIA V4_1_S2S_VH DEFAULT
    LAYER M4 ;
      RECT -0.035 -0.205 0.035 0.065 ;
    LAYER V4 ;
      RECT -0.035 -0.035 0.035 0.035 ;
      RECT -0.035 -0.175 0.035 -0.105 ;
    LAYER M5 ;
      RECT -0.055 -0.185 0.055 0.045 ;
END V4_1_S2S_VH

VIA V4_1_S2V_VH DEFAULT
    LAYER M4 ;
      RECT -0.035 -0.135 0.035 0.135 ;
    LAYER V4 ;
      RECT -0.035 -0.105 0.035 -0.035 ;
      RECT -0.035 0.035 0.035 0.105 ;
    LAYER M5 ;
      RECT -0.055 -0.115 0.055 0.115 ;
END V4_1_S2V_VH

VIA V4_2_VX DEFAULT
    LAYER M4 ;
      RECT -0.035 -0.065 0.035 0.065 ;
    LAYER V4 ;
      RECT -0.035 -0.035 0.035 0.035 ;
    LAYER M5 ;
      RECT -0.05 -0.05 0.05 0.05 ;
END V4_2_VX

VIA V4_2_HX DEFAULT
    LAYER M4 ;
      RECT -0.065 -0.035 0.065 0.035 ;
    LAYER V4 ;
      RECT -0.035 -0.035 0.035 0.035 ;
    LAYER M5 ;
      RECT -0.05 -0.05 0.05 0.05 ;
END V4_2_HX

VIA V4_2_S2H_VX DEFAULT
    LAYER M4 ;
      RECT -0.105 -0.065 0.105 0.065 ;
    LAYER V4 ;
      RECT -0.105 -0.035 -0.035 0.035 ;
      RECT 0.035 -0.035 0.105 0.035 ;
    LAYER M5 ;
      RECT -0.12 -0.05 0.12 0.05 ;
END V4_2_S2H_VX

VIA V4_2_S2E_VX DEFAULT
    LAYER M4 ;
      RECT -0.035 -0.065 0.175 0.065 ;
    LAYER V4 ;
      RECT -0.035 -0.035 0.035 0.035 ;
      RECT 0.105 -0.035 0.175 0.035 ;
    LAYER M5 ;
      RECT -0.05 -0.05 0.19 0.05 ;
END V4_2_S2E_VX

VIA V4_2_S2N_VX DEFAULT
    LAYER M4 ;
      RECT -0.035 -0.065 0.035 0.205 ;
    LAYER V4 ;
      RECT -0.035 -0.035 0.035 0.035 ;
      RECT -0.035 0.105 0.035 0.175 ;
    LAYER M5 ;
      RECT -0.05 -0.05 0.05 0.19 ;
END V4_2_S2N_VX

VIA V4_2_S2W_VX DEFAULT
    LAYER M4 ;
      RECT -0.175 -0.065 0.035 0.065 ;
    LAYER V4 ;
      RECT -0.175 -0.035 -0.105 0.035 ;
      RECT -0.035 -0.035 0.035 0.035 ;
    LAYER M5 ;
      RECT -0.19 -0.05 0.05 0.05 ;
END V4_2_S2W_VX

VIA V4_2_S2S_VX DEFAULT
    LAYER M4 ;
      RECT -0.035 -0.205 0.035 0.065 ;
    LAYER V4 ;
      RECT -0.035 -0.035 0.035 0.035 ;
      RECT -0.035 -0.175 0.035 -0.105 ;
    LAYER M5 ;
      RECT -0.05 -0.19 0.05 0.05 ;
END V4_2_S2S_VX

VIA V4_2_S2V_VX DEFAULT
    LAYER M4 ;
      RECT -0.035 -0.135 0.035 0.135 ;
    LAYER V4 ;
      RECT -0.035 -0.105 0.035 -0.035 ;
      RECT -0.035 0.035 0.035 0.105 ;
    LAYER M5 ;
      RECT -0.05 -0.12 0.05 0.12 ;
END V4_2_S2V_VX

VIA V4_3_VV DEFAULT
    LAYER M4 ;
      RECT -0.045 -0.055 0.045 0.055 ;
    LAYER V4 ;
      RECT -0.035 -0.035 0.035 0.035 ;
    LAYER M5 ;
      RECT -0.035 -0.065 0.035 0.065 ;
END V4_3_VV

VIA V4_3_VH DEFAULT
    LAYER M4 ;
      RECT -0.045 -0.055 0.045 0.055 ;
    LAYER V4 ;
      RECT -0.035 -0.035 0.035 0.035 ;
    LAYER M5 ;
      RECT -0.065 -0.035 0.065 0.035 ;
END V4_3_VH

VIA V4_3_HV DEFAULT
    LAYER M4 ;
      RECT -0.055 -0.045 0.055 0.045 ;
    LAYER V4 ;
      RECT -0.035 -0.035 0.035 0.035 ;
    LAYER M5 ;
      RECT -0.035 -0.065 0.035 0.065 ;
END V4_3_HV

VIA V4_3_HH DEFAULT
    LAYER M4 ;
      RECT -0.055 -0.045 0.055 0.045 ;
    LAYER V4 ;
      RECT -0.035 -0.035 0.035 0.035 ;
    LAYER M5 ;
      RECT -0.065 -0.035 0.065 0.035 ;
END V4_3_HH

VIA V4_3_S2H_VH DEFAULT
    LAYER M4 ;
      RECT -0.115 -0.055 0.115 0.055 ;
    LAYER V4 ;
      RECT -0.105 -0.035 -0.035 0.035 ;
      RECT 0.035 -0.035 0.105 0.035 ;
    LAYER M5 ;
      RECT -0.135 -0.035 0.135 0.035 ;
END V4_3_S2H_VH

VIA V4_3_S2E_VH DEFAULT
    LAYER M4 ;
      RECT -0.045 -0.055 0.185 0.055 ;
    LAYER V4 ;
      RECT -0.035 -0.035 0.035 0.035 ;
      RECT 0.105 -0.035 0.175 0.035 ;
    LAYER M5 ;
      RECT -0.065 -0.035 0.205 0.035 ;
END V4_3_S2E_VH

VIA V4_3_S2N_VH DEFAULT
    LAYER M4 ;
      RECT -0.045 -0.055 0.045 0.195 ;
    LAYER V4 ;
      RECT -0.035 -0.035 0.035 0.035 ;
      RECT -0.035 0.105 0.035 0.175 ;
    LAYER M5 ;
      RECT -0.065 -0.035 0.065 0.175 ;
END V4_3_S2N_VH

VIA V4_3_S2W_VH DEFAULT
    LAYER M4 ;
      RECT -0.185 -0.055 0.045 0.055 ;
    LAYER V4 ;
      RECT -0.175 -0.035 -0.105 0.035 ;
      RECT -0.035 -0.035 0.035 0.035 ;
    LAYER M5 ;
      RECT -0.205 -0.035 0.065 0.035 ;
END V4_3_S2W_VH

VIA V4_3_S2S_VH DEFAULT
    LAYER M4 ;
      RECT -0.045 -0.195 0.045 0.055 ;
    LAYER V4 ;
      RECT -0.035 -0.035 0.035 0.035 ;
      RECT -0.035 -0.175 0.035 -0.105 ;
    LAYER M5 ;
      RECT -0.065 -0.175 0.065 0.035 ;
END V4_3_S2S_VH

VIA V4_3_S2V_VH DEFAULT
    LAYER M4 ;
      RECT -0.045 -0.125 0.045 0.125 ;
    LAYER V4 ;
      RECT -0.035 -0.105 0.035 -0.035 ;
      RECT -0.035 0.035 0.035 0.105 ;
    LAYER M5 ;
      RECT -0.065 -0.105 0.065 0.105 ;
END V4_3_S2V_VH

VIA V4_4_VV DEFAULT
    LAYER M4 ;
      RECT -0.045 -0.055 0.045 0.055 ;
    LAYER V4 ;
      RECT -0.035 -0.035 0.035 0.035 ;
    LAYER M5 ;
      RECT -0.045 -0.055 0.045 0.055 ;
END V4_4_VV

VIA V4_4_VH DEFAULT
    LAYER M4 ;
      RECT -0.045 -0.055 0.045 0.055 ;
    LAYER V4 ;
      RECT -0.035 -0.035 0.035 0.035 ;
    LAYER M5 ;
      RECT -0.055 -0.045 0.055 0.045 ;
END V4_4_VH

VIA V4_4_HV DEFAULT
    LAYER M4 ;
      RECT -0.055 -0.045 0.055 0.045 ;
    LAYER V4 ;
      RECT -0.035 -0.035 0.035 0.035 ;
    LAYER M5 ;
      RECT -0.045 -0.055 0.045 0.055 ;
END V4_4_HV

VIA V4_4_HH DEFAULT
    LAYER M4 ;
      RECT -0.055 -0.045 0.055 0.045 ;
    LAYER V4 ;
      RECT -0.035 -0.035 0.035 0.035 ;
    LAYER M5 ;
      RECT -0.055 -0.045 0.055 0.045 ;
END V4_4_HH

VIA V4_4_S2H_VH DEFAULT
    LAYER M4 ;
      RECT -0.115 -0.055 0.115 0.055 ;
    LAYER V4 ;
      RECT -0.105 -0.035 -0.035 0.035 ;
      RECT 0.035 -0.035 0.105 0.035 ;
    LAYER M5 ;
      RECT -0.125 -0.045 0.125 0.045 ;
END V4_4_S2H_VH

VIA V4_4_S2E_VH DEFAULT
    LAYER M4 ;
      RECT -0.045 -0.055 0.185 0.055 ;
    LAYER V4 ;
      RECT -0.035 -0.035 0.035 0.035 ;
      RECT 0.105 -0.035 0.175 0.035 ;
    LAYER M5 ;
      RECT -0.055 -0.045 0.195 0.045 ;
END V4_4_S2E_VH

VIA V4_4_S2N_VH DEFAULT
    LAYER M4 ;
      RECT -0.045 -0.055 0.045 0.195 ;
    LAYER V4 ;
      RECT -0.035 -0.035 0.035 0.035 ;
      RECT -0.035 0.105 0.035 0.175 ;
    LAYER M5 ;
      RECT -0.055 -0.045 0.055 0.185 ;
END V4_4_S2N_VH

VIA V4_4_S2W_VH DEFAULT
    LAYER M4 ;
      RECT -0.185 -0.055 0.045 0.055 ;
    LAYER V4 ;
      RECT -0.175 -0.035 -0.105 0.035 ;
      RECT -0.035 -0.035 0.035 0.035 ;
    LAYER M5 ;
      RECT -0.195 -0.045 0.055 0.045 ;
END V4_4_S2W_VH

VIA V4_4_S2S_VH DEFAULT
    LAYER M4 ;
      RECT -0.045 -0.195 0.045 0.055 ;
    LAYER V4 ;
      RECT -0.035 -0.035 0.035 0.035 ;
      RECT -0.035 -0.175 0.035 -0.105 ;
    LAYER M5 ;
      RECT -0.055 -0.185 0.055 0.045 ;
END V4_4_S2S_VH

VIA V4_4_S2V_VH DEFAULT
    LAYER M4 ;
      RECT -0.045 -0.125 0.045 0.125 ;
    LAYER V4 ;
      RECT -0.035 -0.105 0.035 -0.035 ;
      RECT -0.035 0.035 0.035 0.105 ;
    LAYER M5 ;
      RECT -0.055 -0.115 0.055 0.115 ;
END V4_4_S2V_VH

VIA V4_5_VX DEFAULT
    LAYER M4 ;
      RECT -0.045 -0.055 0.045 0.055 ;
    LAYER V4 ;
      RECT -0.035 -0.035 0.035 0.035 ;
    LAYER M5 ;
      RECT -0.05 -0.05 0.05 0.05 ;
END V4_5_VX

VIA V4_5_HX DEFAULT
    LAYER M4 ;
      RECT -0.055 -0.045 0.055 0.045 ;
    LAYER V4 ;
      RECT -0.035 -0.035 0.035 0.035 ;
    LAYER M5 ;
      RECT -0.05 -0.05 0.05 0.05 ;
END V4_5_HX

VIA V4_5_S2H_VX DEFAULT
    LAYER M4 ;
      RECT -0.115 -0.055 0.115 0.055 ;
    LAYER V4 ;
      RECT -0.105 -0.035 -0.035 0.035 ;
      RECT 0.035 -0.035 0.105 0.035 ;
    LAYER M5 ;
      RECT -0.12 -0.05 0.12 0.05 ;
END V4_5_S2H_VX

VIA V4_5_S2E_VX DEFAULT
    LAYER M4 ;
      RECT -0.045 -0.055 0.185 0.055 ;
    LAYER V4 ;
      RECT -0.035 -0.035 0.035 0.035 ;
      RECT 0.105 -0.035 0.175 0.035 ;
    LAYER M5 ;
      RECT -0.05 -0.05 0.19 0.05 ;
END V4_5_S2E_VX

VIA V4_5_S2N_VX DEFAULT
    LAYER M4 ;
      RECT -0.045 -0.055 0.045 0.195 ;
    LAYER V4 ;
      RECT -0.035 -0.035 0.035 0.035 ;
      RECT -0.035 0.105 0.035 0.175 ;
    LAYER M5 ;
      RECT -0.05 -0.05 0.05 0.19 ;
END V4_5_S2N_VX

VIA V4_5_S2W_VX DEFAULT
    LAYER M4 ;
      RECT -0.185 -0.055 0.045 0.055 ;
    LAYER V4 ;
      RECT -0.175 -0.035 -0.105 0.035 ;
      RECT -0.035 -0.035 0.035 0.035 ;
    LAYER M5 ;
      RECT -0.19 -0.05 0.05 0.05 ;
END V4_5_S2W_VX

VIA V4_5_S2S_VX DEFAULT
    LAYER M4 ;
      RECT -0.045 -0.195 0.045 0.055 ;
    LAYER V4 ;
      RECT -0.035 -0.035 0.035 0.035 ;
      RECT -0.035 -0.175 0.035 -0.105 ;
    LAYER M5 ;
      RECT -0.05 -0.19 0.05 0.05 ;
END V4_5_S2S_VX

VIA V4_5_S2V_VX DEFAULT
    LAYER M4 ;
      RECT -0.045 -0.125 0.045 0.125 ;
    LAYER V4 ;
      RECT -0.035 -0.105 0.035 -0.035 ;
      RECT -0.035 0.035 0.035 0.105 ;
    LAYER M5 ;
      RECT -0.05 -0.12 0.05 0.12 ;
END V4_5_S2V_VX

VIA V4_6_XV DEFAULT
    LAYER M4 ;
      RECT -0.05 -0.05 0.05 0.05 ;
    LAYER V4 ;
      RECT -0.035 -0.035 0.035 0.035 ;
    LAYER M5 ;
      RECT -0.035 -0.065 0.035 0.065 ;
END V4_6_XV

VIA V4_6_XH DEFAULT
    LAYER M4 ;
      RECT -0.05 -0.05 0.05 0.05 ;
    LAYER V4 ;
      RECT -0.035 -0.035 0.035 0.035 ;
    LAYER M5 ;
      RECT -0.065 -0.035 0.065 0.035 ;
END V4_6_XH

VIA V4_6_S2H_XH DEFAULT
    LAYER M4 ;
      RECT -0.12 -0.05 0.12 0.05 ;
    LAYER V4 ;
      RECT -0.105 -0.035 -0.035 0.035 ;
      RECT 0.035 -0.035 0.105 0.035 ;
    LAYER M5 ;
      RECT -0.135 -0.035 0.135 0.035 ;
END V4_6_S2H_XH

VIA V4_6_S2E_XH DEFAULT
    LAYER M4 ;
      RECT -0.05 -0.05 0.19 0.05 ;
    LAYER V4 ;
      RECT -0.035 -0.035 0.035 0.035 ;
      RECT 0.105 -0.035 0.175 0.035 ;
    LAYER M5 ;
      RECT -0.065 -0.035 0.205 0.035 ;
END V4_6_S2E_XH

VIA V4_6_S2N_XH DEFAULT
    LAYER M4 ;
      RECT -0.05 -0.05 0.05 0.19 ;
    LAYER V4 ;
      RECT -0.035 -0.035 0.035 0.035 ;
      RECT -0.035 0.105 0.035 0.175 ;
    LAYER M5 ;
      RECT -0.065 -0.035 0.065 0.175 ;
END V4_6_S2N_XH

VIA V4_6_S2W_XH DEFAULT
    LAYER M4 ;
      RECT -0.19 -0.05 0.05 0.05 ;
    LAYER V4 ;
      RECT -0.175 -0.035 -0.105 0.035 ;
      RECT -0.035 -0.035 0.035 0.035 ;
    LAYER M5 ;
      RECT -0.205 -0.035 0.065 0.035 ;
END V4_6_S2W_XH

VIA V4_6_S2S_XH DEFAULT
    LAYER M4 ;
      RECT -0.05 -0.19 0.05 0.05 ;
    LAYER V4 ;
      RECT -0.035 -0.035 0.035 0.035 ;
      RECT -0.035 -0.175 0.035 -0.105 ;
    LAYER M5 ;
      RECT -0.065 -0.175 0.065 0.035 ;
END V4_6_S2S_XH

VIA V4_6_S2V_XH DEFAULT
    LAYER M4 ;
      RECT -0.05 -0.12 0.05 0.12 ;
    LAYER V4 ;
      RECT -0.035 -0.105 0.035 -0.035 ;
      RECT -0.035 0.035 0.035 0.105 ;
    LAYER M5 ;
      RECT -0.065 -0.105 0.065 0.105 ;
END V4_6_S2V_XH

VIA V4_7_XV DEFAULT
    LAYER M4 ;
      RECT -0.05 -0.05 0.05 0.05 ;
    LAYER V4 ;
      RECT -0.035 -0.035 0.035 0.035 ;
    LAYER M5 ;
      RECT -0.045 -0.055 0.045 0.055 ;
END V4_7_XV

VIA V4_7_XH DEFAULT
    LAYER M4 ;
      RECT -0.05 -0.05 0.05 0.05 ;
    LAYER V4 ;
      RECT -0.035 -0.035 0.035 0.035 ;
    LAYER M5 ;
      RECT -0.055 -0.045 0.055 0.045 ;
END V4_7_XH

VIA V4_7_S2H_XH DEFAULT
    LAYER M4 ;
      RECT -0.12 -0.05 0.12 0.05 ;
    LAYER V4 ;
      RECT -0.105 -0.035 -0.035 0.035 ;
      RECT 0.035 -0.035 0.105 0.035 ;
    LAYER M5 ;
      RECT -0.125 -0.045 0.125 0.045 ;
END V4_7_S2H_XH

VIA V4_7_S2E_XH DEFAULT
    LAYER M4 ;
      RECT -0.05 -0.05 0.19 0.05 ;
    LAYER V4 ;
      RECT -0.035 -0.035 0.035 0.035 ;
      RECT 0.105 -0.035 0.175 0.035 ;
    LAYER M5 ;
      RECT -0.055 -0.045 0.195 0.045 ;
END V4_7_S2E_XH

VIA V4_7_S2N_XH DEFAULT
    LAYER M4 ;
      RECT -0.05 -0.05 0.05 0.19 ;
    LAYER V4 ;
      RECT -0.035 -0.035 0.035 0.035 ;
      RECT -0.035 0.105 0.035 0.175 ;
    LAYER M5 ;
      RECT -0.055 -0.045 0.055 0.185 ;
END V4_7_S2N_XH

VIA V4_7_S2W_XH DEFAULT
    LAYER M4 ;
      RECT -0.19 -0.05 0.05 0.05 ;
    LAYER V4 ;
      RECT -0.175 -0.035 -0.105 0.035 ;
      RECT -0.035 -0.035 0.035 0.035 ;
    LAYER M5 ;
      RECT -0.195 -0.045 0.055 0.045 ;
END V4_7_S2W_XH

VIA V4_7_S2S_XH DEFAULT
    LAYER M4 ;
      RECT -0.05 -0.19 0.05 0.05 ;
    LAYER V4 ;
      RECT -0.035 -0.035 0.035 0.035 ;
      RECT -0.035 -0.175 0.035 -0.105 ;
    LAYER M5 ;
      RECT -0.055 -0.185 0.055 0.045 ;
END V4_7_S2S_XH

VIA V4_7_S2V_XH DEFAULT
    LAYER M4 ;
      RECT -0.05 -0.12 0.05 0.12 ;
    LAYER V4 ;
      RECT -0.035 -0.105 0.035 -0.035 ;
      RECT -0.035 0.035 0.035 0.105 ;
    LAYER M5 ;
      RECT -0.055 -0.115 0.055 0.115 ;
END V4_7_S2V_XH

VIA V4_8_XX DEFAULT
    LAYER M4 ;
      RECT -0.05 -0.05 0.05 0.05 ;
    LAYER V4 ;
      RECT -0.035 -0.035 0.035 0.035 ;
    LAYER M5 ;
      RECT -0.05 -0.05 0.05 0.05 ;
END V4_8_XX

VIA V4_8_S2H_XX DEFAULT
    LAYER M4 ;
      RECT -0.12 -0.05 0.12 0.05 ;
    LAYER V4 ;
      RECT -0.105 -0.035 -0.035 0.035 ;
      RECT 0.035 -0.035 0.105 0.035 ;
    LAYER M5 ;
      RECT -0.12 -0.05 0.12 0.05 ;
END V4_8_S2H_XX

VIA V4_8_S2E_XX DEFAULT
    LAYER M4 ;
      RECT -0.05 -0.05 0.19 0.05 ;
    LAYER V4 ;
      RECT -0.035 -0.035 0.035 0.035 ;
      RECT 0.105 -0.035 0.175 0.035 ;
    LAYER M5 ;
      RECT -0.05 -0.05 0.19 0.05 ;
END V4_8_S2E_XX

VIA V4_8_S2N_XX DEFAULT
    LAYER M4 ;
      RECT -0.05 -0.05 0.05 0.19 ;
    LAYER V4 ;
      RECT -0.035 -0.035 0.035 0.035 ;
      RECT -0.035 0.105 0.035 0.175 ;
    LAYER M5 ;
      RECT -0.05 -0.05 0.05 0.19 ;
END V4_8_S2N_XX

VIA V4_8_S2W_XX DEFAULT
    LAYER M4 ;
      RECT -0.19 -0.05 0.05 0.05 ;
    LAYER V4 ;
      RECT -0.175 -0.035 -0.105 0.035 ;
      RECT -0.035 -0.035 0.035 0.035 ;
    LAYER M5 ;
      RECT -0.19 -0.05 0.05 0.05 ;
END V4_8_S2W_XX

VIA V4_8_S2S_XX DEFAULT
    LAYER M4 ;
      RECT -0.05 -0.19 0.05 0.05 ;
    LAYER V4 ;
      RECT -0.035 -0.035 0.035 0.035 ;
      RECT -0.035 -0.175 0.035 -0.105 ;
    LAYER M5 ;
      RECT -0.05 -0.19 0.05 0.05 ;
END V4_8_S2S_XX

VIA V4_8_S2V_XX DEFAULT
    LAYER M4 ;
      RECT -0.05 -0.12 0.05 0.12 ;
    LAYER V4 ;
      RECT -0.035 -0.105 0.035 -0.035 ;
      RECT -0.035 0.035 0.035 0.105 ;
    LAYER M5 ;
      RECT -0.05 -0.12 0.05 0.12 ;
END V4_8_S2V_XX

VIA V5_0_VV DEFAULT
    LAYER M5 ;
      RECT -0.035 -0.065 0.035 0.065 ;
    LAYER V5 ;
      RECT -0.035 -0.035 0.035 0.035 ;
    LAYER M6 ;
      RECT -0.035 -0.065 0.035 0.065 ;
END V5_0_VV

VIA V5_0_VH DEFAULT
    LAYER M5 ;
      RECT -0.035 -0.065 0.035 0.065 ;
    LAYER V5 ;
      RECT -0.035 -0.035 0.035 0.035 ;
    LAYER M6 ;
      RECT -0.065 -0.035 0.065 0.035 ;
END V5_0_VH

VIA V5_0_HV DEFAULT
    LAYER M5 ;
      RECT -0.065 -0.035 0.065 0.035 ;
    LAYER V5 ;
      RECT -0.035 -0.035 0.035 0.035 ;
    LAYER M6 ;
      RECT -0.035 -0.065 0.035 0.065 ;
END V5_0_HV

VIA V5_0_HH DEFAULT
    LAYER M5 ;
      RECT -0.065 -0.035 0.065 0.035 ;
    LAYER V5 ;
      RECT -0.035 -0.035 0.035 0.035 ;
    LAYER M6 ;
      RECT -0.065 -0.035 0.065 0.035 ;
END V5_0_HH

VIA V5_0_S2H_VH DEFAULT
    LAYER M5 ;
      RECT -0.105 -0.065 0.105 0.065 ;
    LAYER V5 ;
      RECT -0.105 -0.035 -0.035 0.035 ;
      RECT 0.035 -0.035 0.105 0.035 ;
    LAYER M6 ;
      RECT -0.135 -0.035 0.135 0.035 ;
END V5_0_S2H_VH

VIA V5_0_S2E_VH DEFAULT
    LAYER M5 ;
      RECT -0.035 -0.065 0.175 0.065 ;
    LAYER V5 ;
      RECT -0.035 -0.035 0.035 0.035 ;
      RECT 0.105 -0.035 0.175 0.035 ;
    LAYER M6 ;
      RECT -0.065 -0.035 0.205 0.035 ;
END V5_0_S2E_VH

VIA V5_0_S2N_VH DEFAULT
    LAYER M5 ;
      RECT -0.035 -0.065 0.035 0.205 ;
    LAYER V5 ;
      RECT -0.035 -0.035 0.035 0.035 ;
      RECT -0.035 0.105 0.035 0.175 ;
    LAYER M6 ;
      RECT -0.065 -0.035 0.065 0.175 ;
END V5_0_S2N_VH

VIA V5_0_S2W_VH DEFAULT
    LAYER M5 ;
      RECT -0.175 -0.065 0.035 0.065 ;
    LAYER V5 ;
      RECT -0.175 -0.035 -0.105 0.035 ;
      RECT -0.035 -0.035 0.035 0.035 ;
    LAYER M6 ;
      RECT -0.205 -0.035 0.065 0.035 ;
END V5_0_S2W_VH

VIA V5_0_S2S_VH DEFAULT
    LAYER M5 ;
      RECT -0.035 -0.205 0.035 0.065 ;
    LAYER V5 ;
      RECT -0.035 -0.035 0.035 0.035 ;
      RECT -0.035 -0.175 0.035 -0.105 ;
    LAYER M6 ;
      RECT -0.065 -0.175 0.065 0.035 ;
END V5_0_S2S_VH

VIA V5_0_S2V_VH DEFAULT
    LAYER M5 ;
      RECT -0.035 -0.135 0.035 0.135 ;
    LAYER V5 ;
      RECT -0.035 -0.105 0.035 -0.035 ;
      RECT -0.035 0.035 0.035 0.105 ;
    LAYER M6 ;
      RECT -0.065 -0.105 0.065 0.105 ;
END V5_0_S2V_VH

VIA V5_1_VV DEFAULT
    LAYER M5 ;
      RECT -0.035 -0.065 0.035 0.065 ;
    LAYER V5 ;
      RECT -0.035 -0.035 0.035 0.035 ;
    LAYER M6 ;
      RECT -0.045 -0.055 0.045 0.055 ;
END V5_1_VV

VIA V5_1_VH DEFAULT
    LAYER M5 ;
      RECT -0.035 -0.065 0.035 0.065 ;
    LAYER V5 ;
      RECT -0.035 -0.035 0.035 0.035 ;
    LAYER M6 ;
      RECT -0.055 -0.045 0.055 0.045 ;
END V5_1_VH

VIA V5_1_HV DEFAULT
    LAYER M5 ;
      RECT -0.065 -0.035 0.065 0.035 ;
    LAYER V5 ;
      RECT -0.035 -0.035 0.035 0.035 ;
    LAYER M6 ;
      RECT -0.045 -0.055 0.045 0.055 ;
END V5_1_HV

VIA V5_1_HH DEFAULT
    LAYER M5 ;
      RECT -0.065 -0.035 0.065 0.035 ;
    LAYER V5 ;
      RECT -0.035 -0.035 0.035 0.035 ;
    LAYER M6 ;
      RECT -0.055 -0.045 0.055 0.045 ;
END V5_1_HH

VIA V5_1_S2H_VH DEFAULT
    LAYER M5 ;
      RECT -0.105 -0.065 0.105 0.065 ;
    LAYER V5 ;
      RECT -0.105 -0.035 -0.035 0.035 ;
      RECT 0.035 -0.035 0.105 0.035 ;
    LAYER M6 ;
      RECT -0.125 -0.045 0.125 0.045 ;
END V5_1_S2H_VH

VIA V5_1_S2E_VH DEFAULT
    LAYER M5 ;
      RECT -0.035 -0.065 0.175 0.065 ;
    LAYER V5 ;
      RECT -0.035 -0.035 0.035 0.035 ;
      RECT 0.105 -0.035 0.175 0.035 ;
    LAYER M6 ;
      RECT -0.055 -0.045 0.195 0.045 ;
END V5_1_S2E_VH

VIA V5_1_S2N_VH DEFAULT
    LAYER M5 ;
      RECT -0.035 -0.065 0.035 0.205 ;
    LAYER V5 ;
      RECT -0.035 -0.035 0.035 0.035 ;
      RECT -0.035 0.105 0.035 0.175 ;
    LAYER M6 ;
      RECT -0.055 -0.045 0.055 0.185 ;
END V5_1_S2N_VH

VIA V5_1_S2W_VH DEFAULT
    LAYER M5 ;
      RECT -0.175 -0.065 0.035 0.065 ;
    LAYER V5 ;
      RECT -0.175 -0.035 -0.105 0.035 ;
      RECT -0.035 -0.035 0.035 0.035 ;
    LAYER M6 ;
      RECT -0.195 -0.045 0.055 0.045 ;
END V5_1_S2W_VH

VIA V5_1_S2S_VH DEFAULT
    LAYER M5 ;
      RECT -0.035 -0.205 0.035 0.065 ;
    LAYER V5 ;
      RECT -0.035 -0.035 0.035 0.035 ;
      RECT -0.035 -0.175 0.035 -0.105 ;
    LAYER M6 ;
      RECT -0.055 -0.185 0.055 0.045 ;
END V5_1_S2S_VH

VIA V5_1_S2V_VH DEFAULT
    LAYER M5 ;
      RECT -0.035 -0.135 0.035 0.135 ;
    LAYER V5 ;
      RECT -0.035 -0.105 0.035 -0.035 ;
      RECT -0.035 0.035 0.035 0.105 ;
    LAYER M6 ;
      RECT -0.055 -0.115 0.055 0.115 ;
END V5_1_S2V_VH

VIA V5_2_VX DEFAULT
    LAYER M5 ;
      RECT -0.035 -0.065 0.035 0.065 ;
    LAYER V5 ;
      RECT -0.035 -0.035 0.035 0.035 ;
    LAYER M6 ;
      RECT -0.05 -0.05 0.05 0.05 ;
END V5_2_VX

VIA V5_2_HX DEFAULT
    LAYER M5 ;
      RECT -0.065 -0.035 0.065 0.035 ;
    LAYER V5 ;
      RECT -0.035 -0.035 0.035 0.035 ;
    LAYER M6 ;
      RECT -0.05 -0.05 0.05 0.05 ;
END V5_2_HX

VIA V5_2_S2H_VX DEFAULT
    LAYER M5 ;
      RECT -0.105 -0.065 0.105 0.065 ;
    LAYER V5 ;
      RECT -0.105 -0.035 -0.035 0.035 ;
      RECT 0.035 -0.035 0.105 0.035 ;
    LAYER M6 ;
      RECT -0.12 -0.05 0.12 0.05 ;
END V5_2_S2H_VX

VIA V5_2_S2E_VX DEFAULT
    LAYER M5 ;
      RECT -0.035 -0.065 0.175 0.065 ;
    LAYER V5 ;
      RECT -0.035 -0.035 0.035 0.035 ;
      RECT 0.105 -0.035 0.175 0.035 ;
    LAYER M6 ;
      RECT -0.05 -0.05 0.19 0.05 ;
END V5_2_S2E_VX

VIA V5_2_S2N_VX DEFAULT
    LAYER M5 ;
      RECT -0.035 -0.065 0.035 0.205 ;
    LAYER V5 ;
      RECT -0.035 -0.035 0.035 0.035 ;
      RECT -0.035 0.105 0.035 0.175 ;
    LAYER M6 ;
      RECT -0.05 -0.05 0.05 0.19 ;
END V5_2_S2N_VX

VIA V5_2_S2W_VX DEFAULT
    LAYER M5 ;
      RECT -0.175 -0.065 0.035 0.065 ;
    LAYER V5 ;
      RECT -0.175 -0.035 -0.105 0.035 ;
      RECT -0.035 -0.035 0.035 0.035 ;
    LAYER M6 ;
      RECT -0.19 -0.05 0.05 0.05 ;
END V5_2_S2W_VX

VIA V5_2_S2S_VX DEFAULT
    LAYER M5 ;
      RECT -0.035 -0.205 0.035 0.065 ;
    LAYER V5 ;
      RECT -0.035 -0.035 0.035 0.035 ;
      RECT -0.035 -0.175 0.035 -0.105 ;
    LAYER M6 ;
      RECT -0.05 -0.19 0.05 0.05 ;
END V5_2_S2S_VX

VIA V5_2_S2V_VX DEFAULT
    LAYER M5 ;
      RECT -0.035 -0.135 0.035 0.135 ;
    LAYER V5 ;
      RECT -0.035 -0.105 0.035 -0.035 ;
      RECT -0.035 0.035 0.035 0.105 ;
    LAYER M6 ;
      RECT -0.05 -0.12 0.05 0.12 ;
END V5_2_S2V_VX

VIA V5_3_VV DEFAULT
    LAYER M5 ;
      RECT -0.045 -0.055 0.045 0.055 ;
    LAYER V5 ;
      RECT -0.035 -0.035 0.035 0.035 ;
    LAYER M6 ;
      RECT -0.035 -0.065 0.035 0.065 ;
END V5_3_VV

VIA V5_3_VH DEFAULT
    LAYER M5 ;
      RECT -0.045 -0.055 0.045 0.055 ;
    LAYER V5 ;
      RECT -0.035 -0.035 0.035 0.035 ;
    LAYER M6 ;
      RECT -0.065 -0.035 0.065 0.035 ;
END V5_3_VH

VIA V5_3_HV DEFAULT
    LAYER M5 ;
      RECT -0.055 -0.045 0.055 0.045 ;
    LAYER V5 ;
      RECT -0.035 -0.035 0.035 0.035 ;
    LAYER M6 ;
      RECT -0.035 -0.065 0.035 0.065 ;
END V5_3_HV

VIA V5_3_HH DEFAULT
    LAYER M5 ;
      RECT -0.055 -0.045 0.055 0.045 ;
    LAYER V5 ;
      RECT -0.035 -0.035 0.035 0.035 ;
    LAYER M6 ;
      RECT -0.065 -0.035 0.065 0.035 ;
END V5_3_HH

VIA V5_3_S2H_VH DEFAULT
    LAYER M5 ;
      RECT -0.115 -0.055 0.115 0.055 ;
    LAYER V5 ;
      RECT -0.105 -0.035 -0.035 0.035 ;
      RECT 0.035 -0.035 0.105 0.035 ;
    LAYER M6 ;
      RECT -0.135 -0.035 0.135 0.035 ;
END V5_3_S2H_VH

VIA V5_3_S2E_VH DEFAULT
    LAYER M5 ;
      RECT -0.045 -0.055 0.185 0.055 ;
    LAYER V5 ;
      RECT -0.035 -0.035 0.035 0.035 ;
      RECT 0.105 -0.035 0.175 0.035 ;
    LAYER M6 ;
      RECT -0.065 -0.035 0.205 0.035 ;
END V5_3_S2E_VH

VIA V5_3_S2N_VH DEFAULT
    LAYER M5 ;
      RECT -0.045 -0.055 0.045 0.195 ;
    LAYER V5 ;
      RECT -0.035 -0.035 0.035 0.035 ;
      RECT -0.035 0.105 0.035 0.175 ;
    LAYER M6 ;
      RECT -0.065 -0.035 0.065 0.175 ;
END V5_3_S2N_VH

VIA V5_3_S2W_VH DEFAULT
    LAYER M5 ;
      RECT -0.185 -0.055 0.045 0.055 ;
    LAYER V5 ;
      RECT -0.175 -0.035 -0.105 0.035 ;
      RECT -0.035 -0.035 0.035 0.035 ;
    LAYER M6 ;
      RECT -0.205 -0.035 0.065 0.035 ;
END V5_3_S2W_VH

VIA V5_3_S2S_VH DEFAULT
    LAYER M5 ;
      RECT -0.045 -0.195 0.045 0.055 ;
    LAYER V5 ;
      RECT -0.035 -0.035 0.035 0.035 ;
      RECT -0.035 -0.175 0.035 -0.105 ;
    LAYER M6 ;
      RECT -0.065 -0.175 0.065 0.035 ;
END V5_3_S2S_VH

VIA V5_3_S2V_VH DEFAULT
    LAYER M5 ;
      RECT -0.045 -0.125 0.045 0.125 ;
    LAYER V5 ;
      RECT -0.035 -0.105 0.035 -0.035 ;
      RECT -0.035 0.035 0.035 0.105 ;
    LAYER M6 ;
      RECT -0.065 -0.105 0.065 0.105 ;
END V5_3_S2V_VH

VIA V5_4_VV DEFAULT
    LAYER M5 ;
      RECT -0.045 -0.055 0.045 0.055 ;
    LAYER V5 ;
      RECT -0.035 -0.035 0.035 0.035 ;
    LAYER M6 ;
      RECT -0.045 -0.055 0.045 0.055 ;
END V5_4_VV

VIA V5_4_VH DEFAULT
    LAYER M5 ;
      RECT -0.045 -0.055 0.045 0.055 ;
    LAYER V5 ;
      RECT -0.035 -0.035 0.035 0.035 ;
    LAYER M6 ;
      RECT -0.055 -0.045 0.055 0.045 ;
END V5_4_VH

VIA V5_4_HV DEFAULT
    LAYER M5 ;
      RECT -0.055 -0.045 0.055 0.045 ;
    LAYER V5 ;
      RECT -0.035 -0.035 0.035 0.035 ;
    LAYER M6 ;
      RECT -0.045 -0.055 0.045 0.055 ;
END V5_4_HV

VIA V5_4_HH DEFAULT
    LAYER M5 ;
      RECT -0.055 -0.045 0.055 0.045 ;
    LAYER V5 ;
      RECT -0.035 -0.035 0.035 0.035 ;
    LAYER M6 ;
      RECT -0.055 -0.045 0.055 0.045 ;
END V5_4_HH

VIA V5_4_S2H_VH DEFAULT
    LAYER M5 ;
      RECT -0.115 -0.055 0.115 0.055 ;
    LAYER V5 ;
      RECT -0.105 -0.035 -0.035 0.035 ;
      RECT 0.035 -0.035 0.105 0.035 ;
    LAYER M6 ;
      RECT -0.125 -0.045 0.125 0.045 ;
END V5_4_S2H_VH

VIA V5_4_S2E_VH DEFAULT
    LAYER M5 ;
      RECT -0.045 -0.055 0.185 0.055 ;
    LAYER V5 ;
      RECT -0.035 -0.035 0.035 0.035 ;
      RECT 0.105 -0.035 0.175 0.035 ;
    LAYER M6 ;
      RECT -0.055 -0.045 0.195 0.045 ;
END V5_4_S2E_VH

VIA V5_4_S2N_VH DEFAULT
    LAYER M5 ;
      RECT -0.045 -0.055 0.045 0.195 ;
    LAYER V5 ;
      RECT -0.035 -0.035 0.035 0.035 ;
      RECT -0.035 0.105 0.035 0.175 ;
    LAYER M6 ;
      RECT -0.055 -0.045 0.055 0.185 ;
END V5_4_S2N_VH

VIA V5_4_S2W_VH DEFAULT
    LAYER M5 ;
      RECT -0.185 -0.055 0.045 0.055 ;
    LAYER V5 ;
      RECT -0.175 -0.035 -0.105 0.035 ;
      RECT -0.035 -0.035 0.035 0.035 ;
    LAYER M6 ;
      RECT -0.195 -0.045 0.055 0.045 ;
END V5_4_S2W_VH

VIA V5_4_S2S_VH DEFAULT
    LAYER M5 ;
      RECT -0.045 -0.195 0.045 0.055 ;
    LAYER V5 ;
      RECT -0.035 -0.035 0.035 0.035 ;
      RECT -0.035 -0.175 0.035 -0.105 ;
    LAYER M6 ;
      RECT -0.055 -0.185 0.055 0.045 ;
END V5_4_S2S_VH

VIA V5_4_S2V_VH DEFAULT
    LAYER M5 ;
      RECT -0.045 -0.125 0.045 0.125 ;
    LAYER V5 ;
      RECT -0.035 -0.105 0.035 -0.035 ;
      RECT -0.035 0.035 0.035 0.105 ;
    LAYER M6 ;
      RECT -0.055 -0.115 0.055 0.115 ;
END V5_4_S2V_VH

VIA V5_5_VX DEFAULT
    LAYER M5 ;
      RECT -0.045 -0.055 0.045 0.055 ;
    LAYER V5 ;
      RECT -0.035 -0.035 0.035 0.035 ;
    LAYER M6 ;
      RECT -0.05 -0.05 0.05 0.05 ;
END V5_5_VX

VIA V5_5_HX DEFAULT
    LAYER M5 ;
      RECT -0.055 -0.045 0.055 0.045 ;
    LAYER V5 ;
      RECT -0.035 -0.035 0.035 0.035 ;
    LAYER M6 ;
      RECT -0.05 -0.05 0.05 0.05 ;
END V5_5_HX

VIA V5_5_S2H_VX DEFAULT
    LAYER M5 ;
      RECT -0.115 -0.055 0.115 0.055 ;
    LAYER V5 ;
      RECT -0.105 -0.035 -0.035 0.035 ;
      RECT 0.035 -0.035 0.105 0.035 ;
    LAYER M6 ;
      RECT -0.12 -0.05 0.12 0.05 ;
END V5_5_S2H_VX

VIA V5_5_S2E_VX DEFAULT
    LAYER M5 ;
      RECT -0.045 -0.055 0.185 0.055 ;
    LAYER V5 ;
      RECT -0.035 -0.035 0.035 0.035 ;
      RECT 0.105 -0.035 0.175 0.035 ;
    LAYER M6 ;
      RECT -0.05 -0.05 0.19 0.05 ;
END V5_5_S2E_VX

VIA V5_5_S2N_VX DEFAULT
    LAYER M5 ;
      RECT -0.045 -0.055 0.045 0.195 ;
    LAYER V5 ;
      RECT -0.035 -0.035 0.035 0.035 ;
      RECT -0.035 0.105 0.035 0.175 ;
    LAYER M6 ;
      RECT -0.05 -0.05 0.05 0.19 ;
END V5_5_S2N_VX

VIA V5_5_S2W_VX DEFAULT
    LAYER M5 ;
      RECT -0.185 -0.055 0.045 0.055 ;
    LAYER V5 ;
      RECT -0.175 -0.035 -0.105 0.035 ;
      RECT -0.035 -0.035 0.035 0.035 ;
    LAYER M6 ;
      RECT -0.19 -0.05 0.05 0.05 ;
END V5_5_S2W_VX

VIA V5_5_S2S_VX DEFAULT
    LAYER M5 ;
      RECT -0.045 -0.195 0.045 0.055 ;
    LAYER V5 ;
      RECT -0.035 -0.035 0.035 0.035 ;
      RECT -0.035 -0.175 0.035 -0.105 ;
    LAYER M6 ;
      RECT -0.05 -0.19 0.05 0.05 ;
END V5_5_S2S_VX

VIA V5_5_S2V_VX DEFAULT
    LAYER M5 ;
      RECT -0.045 -0.125 0.045 0.125 ;
    LAYER V5 ;
      RECT -0.035 -0.105 0.035 -0.035 ;
      RECT -0.035 0.035 0.035 0.105 ;
    LAYER M6 ;
      RECT -0.05 -0.12 0.05 0.12 ;
END V5_5_S2V_VX

VIA V5_6_XV DEFAULT
    LAYER M5 ;
      RECT -0.05 -0.05 0.05 0.05 ;
    LAYER V5 ;
      RECT -0.035 -0.035 0.035 0.035 ;
    LAYER M6 ;
      RECT -0.035 -0.065 0.035 0.065 ;
END V5_6_XV

VIA V5_6_XH DEFAULT
    LAYER M5 ;
      RECT -0.05 -0.05 0.05 0.05 ;
    LAYER V5 ;
      RECT -0.035 -0.035 0.035 0.035 ;
    LAYER M6 ;
      RECT -0.065 -0.035 0.065 0.035 ;
END V5_6_XH

VIA V5_6_S2H_XH DEFAULT
    LAYER M5 ;
      RECT -0.12 -0.05 0.12 0.05 ;
    LAYER V5 ;
      RECT -0.105 -0.035 -0.035 0.035 ;
      RECT 0.035 -0.035 0.105 0.035 ;
    LAYER M6 ;
      RECT -0.135 -0.035 0.135 0.035 ;
END V5_6_S2H_XH

VIA V5_6_S2E_XH DEFAULT
    LAYER M5 ;
      RECT -0.05 -0.05 0.19 0.05 ;
    LAYER V5 ;
      RECT -0.035 -0.035 0.035 0.035 ;
      RECT 0.105 -0.035 0.175 0.035 ;
    LAYER M6 ;
      RECT -0.065 -0.035 0.205 0.035 ;
END V5_6_S2E_XH

VIA V5_6_S2N_XH DEFAULT
    LAYER M5 ;
      RECT -0.05 -0.05 0.05 0.19 ;
    LAYER V5 ;
      RECT -0.035 -0.035 0.035 0.035 ;
      RECT -0.035 0.105 0.035 0.175 ;
    LAYER M6 ;
      RECT -0.065 -0.035 0.065 0.175 ;
END V5_6_S2N_XH

VIA V5_6_S2W_XH DEFAULT
    LAYER M5 ;
      RECT -0.19 -0.05 0.05 0.05 ;
    LAYER V5 ;
      RECT -0.175 -0.035 -0.105 0.035 ;
      RECT -0.035 -0.035 0.035 0.035 ;
    LAYER M6 ;
      RECT -0.205 -0.035 0.065 0.035 ;
END V5_6_S2W_XH

VIA V5_6_S2S_XH DEFAULT
    LAYER M5 ;
      RECT -0.05 -0.19 0.05 0.05 ;
    LAYER V5 ;
      RECT -0.035 -0.035 0.035 0.035 ;
      RECT -0.035 -0.175 0.035 -0.105 ;
    LAYER M6 ;
      RECT -0.065 -0.175 0.065 0.035 ;
END V5_6_S2S_XH

VIA V5_6_S2V_XH DEFAULT
    LAYER M5 ;
      RECT -0.05 -0.12 0.05 0.12 ;
    LAYER V5 ;
      RECT -0.035 -0.105 0.035 -0.035 ;
      RECT -0.035 0.035 0.035 0.105 ;
    LAYER M6 ;
      RECT -0.065 -0.105 0.065 0.105 ;
END V5_6_S2V_XH

VIA V5_7_XV DEFAULT
    LAYER M5 ;
      RECT -0.05 -0.05 0.05 0.05 ;
    LAYER V5 ;
      RECT -0.035 -0.035 0.035 0.035 ;
    LAYER M6 ;
      RECT -0.045 -0.055 0.045 0.055 ;
END V5_7_XV

VIA V5_7_XH DEFAULT
    LAYER M5 ;
      RECT -0.05 -0.05 0.05 0.05 ;
    LAYER V5 ;
      RECT -0.035 -0.035 0.035 0.035 ;
    LAYER M6 ;
      RECT -0.055 -0.045 0.055 0.045 ;
END V5_7_XH

VIA V5_7_S2H_XH DEFAULT
    LAYER M5 ;
      RECT -0.12 -0.05 0.12 0.05 ;
    LAYER V5 ;
      RECT -0.105 -0.035 -0.035 0.035 ;
      RECT 0.035 -0.035 0.105 0.035 ;
    LAYER M6 ;
      RECT -0.125 -0.045 0.125 0.045 ;
END V5_7_S2H_XH

VIA V5_7_S2E_XH DEFAULT
    LAYER M5 ;
      RECT -0.05 -0.05 0.19 0.05 ;
    LAYER V5 ;
      RECT -0.035 -0.035 0.035 0.035 ;
      RECT 0.105 -0.035 0.175 0.035 ;
    LAYER M6 ;
      RECT -0.055 -0.045 0.195 0.045 ;
END V5_7_S2E_XH

VIA V5_7_S2N_XH DEFAULT
    LAYER M5 ;
      RECT -0.05 -0.05 0.05 0.19 ;
    LAYER V5 ;
      RECT -0.035 -0.035 0.035 0.035 ;
      RECT -0.035 0.105 0.035 0.175 ;
    LAYER M6 ;
      RECT -0.055 -0.045 0.055 0.185 ;
END V5_7_S2N_XH

VIA V5_7_S2W_XH DEFAULT
    LAYER M5 ;
      RECT -0.19 -0.05 0.05 0.05 ;
    LAYER V5 ;
      RECT -0.175 -0.035 -0.105 0.035 ;
      RECT -0.035 -0.035 0.035 0.035 ;
    LAYER M6 ;
      RECT -0.195 -0.045 0.055 0.045 ;
END V5_7_S2W_XH

VIA V5_7_S2S_XH DEFAULT
    LAYER M5 ;
      RECT -0.05 -0.19 0.05 0.05 ;
    LAYER V5 ;
      RECT -0.035 -0.035 0.035 0.035 ;
      RECT -0.035 -0.175 0.035 -0.105 ;
    LAYER M6 ;
      RECT -0.055 -0.185 0.055 0.045 ;
END V5_7_S2S_XH

VIA V5_7_S2V_XH DEFAULT
    LAYER M5 ;
      RECT -0.05 -0.12 0.05 0.12 ;
    LAYER V5 ;
      RECT -0.035 -0.105 0.035 -0.035 ;
      RECT -0.035 0.035 0.035 0.105 ;
    LAYER M6 ;
      RECT -0.055 -0.115 0.055 0.115 ;
END V5_7_S2V_XH

VIA V5_8_XX DEFAULT
    LAYER M5 ;
      RECT -0.05 -0.05 0.05 0.05 ;
    LAYER V5 ;
      RECT -0.035 -0.035 0.035 0.035 ;
    LAYER M6 ;
      RECT -0.05 -0.05 0.05 0.05 ;
END V5_8_XX

VIA V5_8_S2H_XX DEFAULT
    LAYER M5 ;
      RECT -0.12 -0.05 0.12 0.05 ;
    LAYER V5 ;
      RECT -0.105 -0.035 -0.035 0.035 ;
      RECT 0.035 -0.035 0.105 0.035 ;
    LAYER M6 ;
      RECT -0.12 -0.05 0.12 0.05 ;
END V5_8_S2H_XX

VIA V5_8_S2E_XX DEFAULT
    LAYER M5 ;
      RECT -0.05 -0.05 0.19 0.05 ;
    LAYER V5 ;
      RECT -0.035 -0.035 0.035 0.035 ;
      RECT 0.105 -0.035 0.175 0.035 ;
    LAYER M6 ;
      RECT -0.05 -0.05 0.19 0.05 ;
END V5_8_S2E_XX

VIA V5_8_S2N_XX DEFAULT
    LAYER M5 ;
      RECT -0.05 -0.05 0.05 0.19 ;
    LAYER V5 ;
      RECT -0.035 -0.035 0.035 0.035 ;
      RECT -0.035 0.105 0.035 0.175 ;
    LAYER M6 ;
      RECT -0.05 -0.05 0.05 0.19 ;
END V5_8_S2N_XX

VIA V5_8_S2W_XX DEFAULT
    LAYER M5 ;
      RECT -0.19 -0.05 0.05 0.05 ;
    LAYER V5 ;
      RECT -0.175 -0.035 -0.105 0.035 ;
      RECT -0.035 -0.035 0.035 0.035 ;
    LAYER M6 ;
      RECT -0.19 -0.05 0.05 0.05 ;
END V5_8_S2W_XX

VIA V5_8_S2S_XX DEFAULT
    LAYER M5 ;
      RECT -0.05 -0.19 0.05 0.05 ;
    LAYER V5 ;
      RECT -0.035 -0.035 0.035 0.035 ;
      RECT -0.035 -0.175 0.035 -0.105 ;
    LAYER M6 ;
      RECT -0.05 -0.19 0.05 0.05 ;
END V5_8_S2S_XX

VIA V5_8_S2V_XX DEFAULT
    LAYER M5 ;
      RECT -0.05 -0.12 0.05 0.12 ;
    LAYER V5 ;
      RECT -0.035 -0.105 0.035 -0.035 ;
      RECT -0.035 0.035 0.035 0.105 ;
    LAYER M6 ;
      RECT -0.05 -0.12 0.05 0.12 ;
END V5_8_S2V_XX

VIA TV1 DEFAULT
    LAYER M6 ;
      RECT -0.230000 -0.190000 0.230000 0.190000 ;
    LAYER TV1 ;
      RECT -0.180000 -0.180000 0.180000 0.180000 ;
    LAYER TM1 ;
      RECT -0.200000 -0.210000 0.200000 0.210000 ; 
    RESISTANCE 0.300000 ;
END TV1

VIA TV1_alt DEFAULT 
    LAYER M6 ;
      RECT -0.230000 -0.190000 0.230000 0.190000 ;
    LAYER TV1 ;
      RECT -0.180000 -0.180000 0.180000 0.180000 ;
    LAYER TM1 ;
      RECT -0.210000 -0.200000 0.210000 0.200000 ; 
    RESISTANCE 0.300000 ;
END TV1_alt

VIA TV1_r90 DEFAULT 
   LAYER M6 ;
      RECT -0.190000 -0.230000 0.190000 0.230000 ;
     LAYER TV1 ;
      RECT -0.180000 -0.180000 0.180000 0.180000 ;
    LAYER TM1 ;
      RECT -0.210000 -0.200000 0.210000 0.200000 ; 
    RESISTANCE 0.300000 ;
END TV1_r90

VIA TV1_alt_r90 DEFAULT 
    LAYER M6 ;
      RECT -0.190000 -0.230000 0.190000 0.230000 ;
    LAYER TV1 ;
      RECT -0.180000 -0.180000 0.180000 0.180000 ;
    LAYER TM1 ;
      RECT -0.200000 -0.210000 0.200000 0.210000 ; 
    RESISTANCE 0.300000 ;
END TV1_alt_r90

VIA TV2 DEFAULT
    LAYER TM1 ;
      RECT -0.230000 -0.200000 0.230000 0.200000 ;
    LAYER TV2 ;
      RECT -0.180000 -0.180000 0.180000 0.180000 ;
    LAYER TM2 ;
      RECT -0.200000 -0.210000 0.200000 0.210000 ; 
    RESISTANCE 0.300000 ;
END TV2

VIA TV2_alt DEFAULT 
    LAYER TM1 ;
      RECT -0.230000 -0.200000 0.230000 0.200000 ;
    LAYER TV2 ;
      RECT -0.180000 -0.180000 0.180000 0.180000 ;
    LAYER TM2 ;
      RECT -0.210000 -0.200000 0.210000 0.200000 ; 
    RESISTANCE 0.300000 ;
END TV2_alt

VIA TV2_r90 DEFAULT 
  LAYER TM1 ;
      RECT -0.200000 -0.230000 0.200000 0.230000 ;
     LAYER TV2 ;
      RECT -0.180000 -0.180000 0.180000 0.180000 ;
    LAYER TM2 ;
      RECT -0.210000 -0.200000 0.210000 0.200000 ; 
    RESISTANCE 0.300000 ;
END TV2_r90

VIA TV2_alt_r90 DEFAULT 
    LAYER TM1 ;
      RECT -0.200000 -0.230000 0.200000 0.230000 ;
    LAYER TV2 ;
      RECT -0.180000 -0.180000 0.180000 0.180000 ;
    LAYER TM2 ;
      RECT -0.200000 -0.210000 0.200000 0.210000 ; 
    RESISTANCE 0.300000 ;
END TV2_alt_r90

VIA PA DEFAULT
    LAYER TM2 ;
      RECT -1.500000 -1.500000 1.500000 1.500000 ;
    LAYER PA ;
      RECT -1.000000 -1.000000 1.000000 1.000000 ;
    LAYER ALPA ;
      RECT -1.500000 -1.500000 1.500000 1.500000 ;
    RESISTANCE 0.300000 ;
END PA

VIA TV1_2cut_E DEFAULT 
    LAYER M6 ; 
        RECT -0.23000 -0.19000 0.95000 0.19000 ;
    LAYER TV1 ; 
        RECT -0.18000 -0.18000 0.18000 0.18000 ;
        RECT 0.540000 -0.18000 0.90000 0.18000 ;
    LAYER TM1 ; 
        RECT -0.21000 -0.20000 0.93000 0.20000 ;
    RESISTANCE 0.150000 ;
END TV1_2cut_E

VIA TV1_2cut_W DEFAULT 
    LAYER M6 ; 
        RECT -0.95000 -0.19000 0.23000 0.19000 ;
    LAYER TV1 ; 
        RECT -0.18000 -0.18000 0.18000 0.18000 ;
        RECT -0.90000 -0.18000 -0.5400 0.18000 ;
    LAYER TM1 ; 
        RECT -0.93000 -0.20000 0.21000 0.20000 ;
    RESISTANCE 0.150000 ;
END TV1_2cut_W

VIA TV1_2cut_N DEFAULT 
    LAYER M6 ; 
        RECT -0.19000 -0.23000 0.19000 0.95000 ;
    LAYER TV1 ; 
        RECT -0.18000 -0.18000 0.18000 0.18000 ;
        RECT -0.18000 0.540000 0.18000 0.90000 ;
    LAYER TM1 ; 
        RECT -0.20000 -0.21000 0.20000 0.93000 ;
    RESISTANCE 0.150000 ;
END TV1_2cut_N

VIA TV1_2cut_S DEFAULT 
    LAYER M6 ; 
        RECT -0.19000 -0.95000 0.19000 0.23000 ;
    LAYER TV1 ; 
        RECT -0.18000 -0.18000 0.18000 0.18000 ;
        RECT -0.18000 -0.90000 0.18000 -0.5400 ;
    LAYER TM1 ; 
        RECT -0.20000 -0.93000 0.20000 0.21000 ;
    RESISTANCE 0.150000 ;
END TV1_2cut_S

VIA TV2_2cut_E DEFAULT 
    LAYER TM1 ; 
        RECT -0.23000 -0.20000 0.95000 0.20000 ;
    LAYER TV2 ; 
        RECT -0.18000 -0.18000 0.18000 0.18000 ;
        RECT 0.540000 -0.18000 0.90000 0.18000 ;
    LAYER TM2 ; 
        RECT -0.21000 -0.20000 0.93000 0.20000 ;
    RESISTANCE 0.150000 ;
END TV2_2cut_E

VIA TV2_2cut_W DEFAULT 
    LAYER TM1 ; 
        RECT -0.95000 -0.20000 0.23000 0.20000 ;
    LAYER TV2 ; 
        RECT -0.18000 -0.18000 0.18000 0.18000 ;
        RECT -0.90000 -0.18000 -0.5400 0.18000 ;
    LAYER TM2 ; 
        RECT -0.93000 -0.20000 0.21000 0.20000 ;
    RESISTANCE 0.150000 ;
END TV2_2cut_W

VIA TV2_2cut_N DEFAULT 
    LAYER TM1 ; 
        RECT -0.20000 -0.23000 0.20000 0.95000 ;
    LAYER TV2 ; 
        RECT -0.18000 -0.18000 0.18000 0.18000 ;
        RECT -0.18000 0.540000 0.18000 0.90000 ;
    LAYER TM2 ; 
        RECT -0.20000 -0.21000 0.20000 0.93000 ;
    RESISTANCE 0.150000 ;
END TV2_2cut_N

VIA TV2_2cut_S DEFAULT 
    LAYER TM1 ; 
        RECT -0.20000 -0.95000 0.20000 0.23000 ;
    LAYER TV2 ; 
        RECT -0.18000 -0.18000 0.18000 0.18000 ;
        RECT -0.18000 -0.90000 0.18000 -0.5400 ;
    LAYER TM2 ; 
        RECT -0.20000 -0.93000 0.20000 0.21000 ;
    RESISTANCE 0.150000 ;
END TV2_2cut_S

VIA PA_2cut_E DEFAULT 
    LAYER TM2 ; 
        RECT -1.50000 -1.50000 5.50000 1.50000 ;
    LAYER PA ; 
        RECT -1.00000 -1.00000 1.00000 1.00000 ;
        RECT 3.000000 -1.00000 5.00000 1.00000 ;
    LAYER ALPA ; 
        RECT -1.50000 -1.50000 5.50000 1.50000 ;
    RESISTANCE 0.150000 ;
END PA_2cut_E

VIA PA_2cut_W DEFAULT 
    LAYER TM2 ; 
        RECT -5.50000 -1.50000 1.50000 1.50000 ;
    LAYER PA ; 
        RECT -1.00000 -1.00000 1.00000 1.00000 ;
        RECT -5.00000 -1.00000 -3.0000 1.00000 ;
    LAYER ALPA ; 
        RECT -5.50000 -1.50000 1.50000 1.50000 ;
    RESISTANCE 0.150000 ;
END PA_2cut_W

VIA PA_2cut_N DEFAULT 
    LAYER TM2 ; 
        RECT -1.50000 -1.50000 1.50000 5.50000 ;
    LAYER PA ; 
        RECT -1.00000 -1.00000 1.00000 1.00000 ;
        RECT -1.00000 3.000000 1.00000 5.00000 ;
    LAYER ALPA ; 
        RECT -1.50000 -1.50000 1.50000 5.50000 ;
    RESISTANCE 0.150000 ;
END PA_2cut_N

VIA PA_2cut_S DEFAULT 
    LAYER TM2 ; 
        RECT -1.50000 -5.50000 1.50000 1.50000 ;
    LAYER PA ; 
        RECT -1.00000 -1.00000 1.00000 1.00000 ;
        RECT -1.00000 -5.00000 1.00000 -3.0000 ;
    LAYER ALPA ; 
        RECT -1.50000 -5.50000 1.50000 1.50000 ;
    RESISTANCE 0.150000 ;
END PA_2cut_S

VIARULE VIA1ARRAY GENERATE
    LAYER M1 ;
        ENCLOSURE 0.03 0.000 ;
    LAYER M2 ;
        ENCLOSURE 0.03 0.000 ;
    LAYER V1 ;
        RECT -0.035 -0.035 0.035 0.035 ;
        SPACING 0.160 BY 0.160 ;
END VIA1ARRAY

VIARULE VIA2ARRAY GENERATE
    LAYER M2 ;
        ENCLOSURE 0.03 0.000 ;
    LAYER M3 ;
        ENCLOSURE 0.03 0.000 ;
    LAYER V2 ;
       RECT -0.035 -0.035 0.035 0.035 ;
       SPACING 0.160 BY 0.160 ; 
END VIA2ARRAY

VIARULE VIA3ARRAY GENERATE
    LAYER M3 ;
        ENCLOSURE 0.03 0.000 ;
    LAYER M4 ;
        ENCLOSURE 0.03 0.000 ;
    LAYER V3 ;
        RECT -0.035 -0.035 0.035 0.035 ;
        SPACING 0.160 BY 0.160 ;
END VIA3ARRAY

VIARULE VIA4ARRAY GENERATE
    LAYER M4 ;
        ENCLOSURE 0.03 0.000 ;
    LAYER M5 ;
        ENCLOSURE 0.03 0.000 ;
    LAYER V4 ;
        RECT -0.035 -0.035 0.035 0.035 ;
        SPACING 0.160 BY 0.160 ;
END VIA4ARRAY

VIARULE VIA5ARRAY GENERATE
    LAYER M5 ;
        ENCLOSURE 0.03 0.000 ;
    LAYER M6 ;
        ENCLOSURE 0.03 0.000 ;
    LAYER V5 ;
        RECT -0.035 -0.035 0.035 0.035 ;
        SPACING 0.160 BY 0.160 ;
END VIA5ARRAY

VIARULE TV1ARRAY GENERATE
    LAYER M6 ;
        ENCLOSURE 0.05 0.01 ;
    LAYER TM1 ;
        ENCLOSURE 0.03 0.02 ;
    LAYER TV1 ;
        RECT -0.180 -0.180 0.180 0.180 ;
        SPACING 0.860 BY 0.860 ;
END TV1ARRAY

VIARULE TV2ARRAY GENERATE
    LAYER TM1 ;
        ENCLOSURE 0.05 0.01 ;
    LAYER TM2 ;
        ENCLOSURE 0.03 0.02 ;
    LAYER TV2 ;
        RECT -0.180 -0.180 0.180 0.180 ;
        SPACING 0.860 BY 0.860 ;
END TV2ARRAY

VIARULE PAARRAY GENERATE
    LAYER TM2 ;
        ENCLOSURE 0.50 0.50 ;
    LAYER ALPA ;
        ENCLOSURE 0.50 0.50 ;
    LAYER PA ;
        RECT -1.000 -1.000 1.000 1.000 ;
        SPACING 4.000 BY 4.000 ;
END PAARRAY

END LIBRARY

